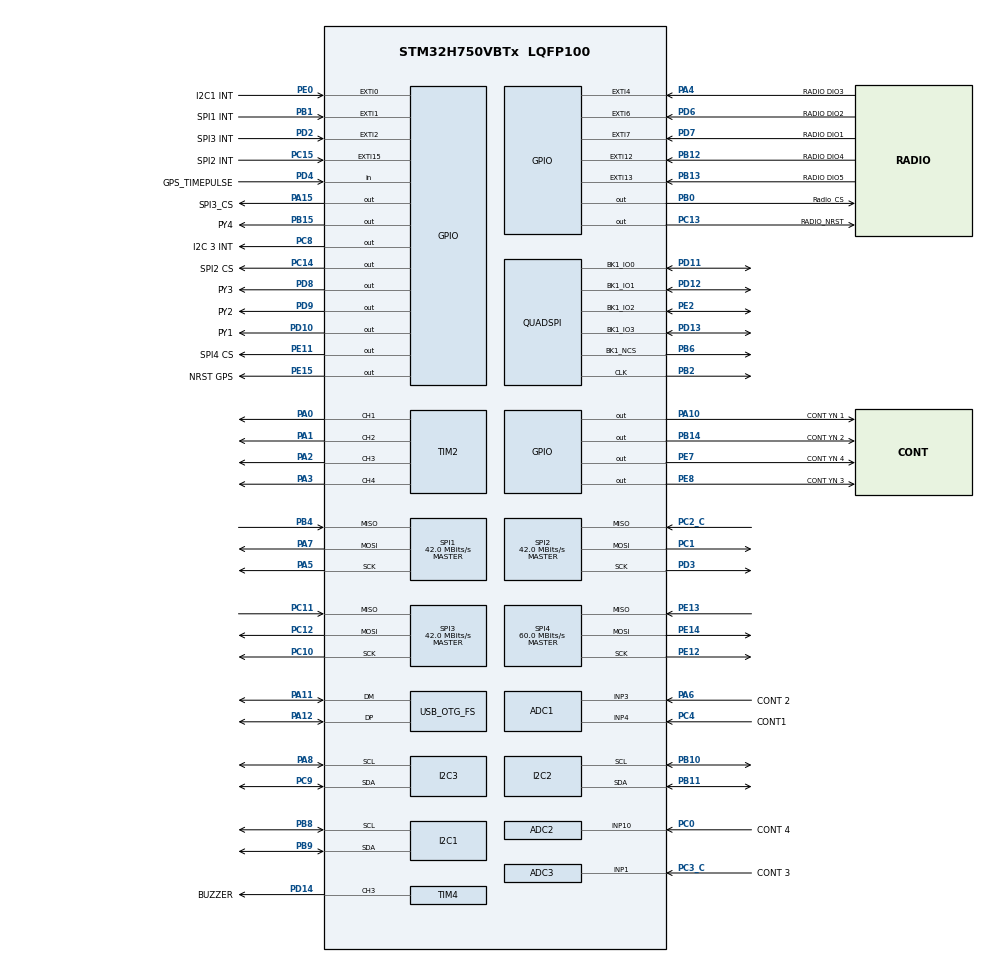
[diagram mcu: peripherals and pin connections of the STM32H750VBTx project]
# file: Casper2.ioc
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ADC1.Channel-2\#ChannelRegularConversion=ADC_CHANNEL_3
ADC1.ClockPrescaler=ADC_CLOCK_ASYNC_DIV2
ADC1.NbrOfConversionFlag=1
ADC1.OffsetNumber-2\#ChannelRegularConversion=ADC_OFFSET_NONE
ADC1.OffsetSignedSaturation-2\#ChannelRegularConversion=DISABLE
ADC1.Rank-2\#ChannelRegularConversion=1
ADC1.SamplingTime-2\#ChannelRegularConversion=ADC_SAMPLETIME_1CYCLE_5
ADC1.master=1
ADC2.Channel-1\#ChannelRegularConversion=ADC_CHANNEL_10
ADC2.ClockPrescaler=ADC_CLOCK_ASYNC_DIV2
ADC2.NbrOfConversionFlag=1
ADC2.OffsetNumber-1\#ChannelRegularConversion=ADC_OFFSET_NONE
ADC2.OffsetSignedSaturation-1\#ChannelRegularConversion=DISABLE
ADC2.Rank-1\#ChannelRegularConversion=1
ADC2.SamplingTime-1\#ChannelRegularConversion=ADC_SAMPLETIME_1CYCLE_5
ADC3.Channel-1\#ChannelRegularConversion=ADC_CHANNEL_1
ADC3.ClockPrescaler=ADC_CLOCK_ASYNC_DIV2
ADC3.NbrOfConversionFlag=1
ADC3.OffsetNumber-1\#ChannelRegularConversion=ADC_OFFSET_NONE
ADC3.OffsetSignedSaturation-1\#ChannelRegularConversion=DISABLE
ADC3.Rank-1\#ChannelRegularConversion=1
ADC3.SamplingTime-1\#ChannelRegularConversion=ADC_SAMPLETIME_1CYCLE_5
CORTEX_M7.default_mode_Activation=1
I2C1.Timing=0x10707DBC
I2C2.Timing=0x10707DBC
I2C3.Timing=0x10707DBC
Mcu.Family=STM32H7
Mcu.Name=STM32H750VBTx
Mcu.Package=LQFP100
NVIC.OTG_FS_EP1_IN_IRQn=true\:0\:0\:false\:false\:true\:true\:true\:true
NVIC.OTG_FS_EP1_OUT_IRQn=true\:0\:0\:false\:false\:true\:true\:true\:true
NVIC.OTG_FS_IRQn=true\:0\:0\:false\:false\:true\:true\:true\:true
NVIC.PriorityGroup=NVIC_PRIORITYGROUP_4
PA0.Signal=S_TIM2_CH1_ETR
PA1.Signal=S_TIM2_CH2
PA10.GPIO_Label=CONT YN 1
PA10.Signal=GPIO_Output
PA11.Mode=Device_Only
PA11.Signal=USB_OTG_FS_DM
PA12.Mode=Device_Only
PA12.Signal=USB_OTG_FS_DP
PA13\ (JTMS/SWDIO).Mode=Trace_Asynchronous_SW
PA13\ (JTMS/SWDIO).Signal=DEBUG_JTMS-SWDIO
PA14\ (JTCK/SWCLK).Mode=Trace_Asynchronous_SW
PA14\ (JTCK/SWCLK).Signal=DEBUG_JTCK-SWCLK
PA15\ (JTDI).GPIO_Label=SPI3_CS
PA15\ (JTDI).Signal=GPIO_Output
PA2.Signal=S_TIM2_CH3
PA3.Signal=S_TIM2_CH4
PA4.GPIO_Label=RADIO DIO3
PA4.Signal=GPXTI4
PA5.Mode=Full_Duplex_Master
PA5.Signal=SPI1_SCK
PA6.GPIO_Label=CONT 2
PA6.Signal=ADCx_INP3
PA7.Mode=Full_Duplex_Master
PA7.Signal=SPI1_MOSI
PA8.Mode=I2C
PA8.Signal=I2C3_SCL
PB0.GPIO_Label=Radio_CS
PB0.Signal=GPIO_Output
PB1.GPIO_Label=SPI1 INT
PB1.Signal=GPXTI1
PB10.Mode=I2C
PB10.Signal=I2C2_SCL
PB11.Mode=I2C
PB11.Signal=I2C2_SDA
PB12.GPIO_Label=RADIO DIO4
PB12.Signal=GPXTI12
PB13.GPIO_Label=RADIO DIO5
PB13.Signal=GPXTI13
PB14.GPIO_Label=CONT YN 2
PB14.Signal=GPIO_Output
PB15.GPIO_Label=PY4
PB15.Signal=GPIO_Output
PB2.Mode=Single Bank 1
PB2.Signal=QUADSPI_CLK
PB3\ (JTDO/TRACESWO).Mode=Trace_Asynchronous_SW
PB3\ (JTDO/TRACESWO).Signal=DEBUG_JTDO-SWO
PB4\ (NJTRST).Mode=Full_Duplex_Master
PB4\ (NJTRST).Signal=SPI1_MISO
PB6.Mode=Single Bank 1
PB6.Signal=QUADSPI_BK1_NCS
PB8.Mode=I2C
PB8.Signal=I2C1_SCL
PB9.Mode=I2C
PB9.Signal=I2C1_SDA
PC0.GPIO_Label=CONT 4
PC0.Signal=ADCx_INP10
PC1.Mode=Full_Duplex_Master
PC1.Signal=SPI2_MOSI
PC10.Mode=Full_Duplex_Master
PC10.Signal=SPI3_SCK
PC11.Mode=Full_Duplex_Master
PC11.Signal=SPI3_MISO
PC12.Mode=Full_Duplex_Master
PC12.Signal=SPI3_MOSI
PC13.GPIO_Label=RADIO_NRST
PC13.GPIO_PuPd=GPIO_PULLUP
PC13.Signal=GPIO_Output
PC14-OSC32_IN\ (OSC32_IN).GPIO_Label=SPI2 CS
PC14-OSC32_IN\ (OSC32_IN).Signal=GPIO_Output
PC15-OSC32_OUT\ (OSC32_OUT).GPIO_Label=SPI2 INT
PC15-OSC32_OUT\ (OSC32_OUT).Signal=GPXTI15
PC2_C.Mode=Full_Duplex_Master
PC2_C.Signal=SPI2_MISO
PC3_C.GPIO_Label=CONT 3
PC3_C.Mode=IN1-Single-Ended
PC3_C.Signal=ADC3_INP1
PC4.GPIO_Label=CONT1
PC4.Signal=ADCx_INP4
PC8.GPIO_Label=I2C 3 INT
PC8.Signal=GPIO_Output
PC9.Mode=I2C
PC9.Signal=I2C3_SDA
PD10.GPIO_Label=PY1
PD10.Signal=GPIO_Output
PD11.Mode=Single Bank 1
PD11.Signal=QUADSPI_BK1_IO0
PD12.Mode=Single Bank 1
PD12.Signal=QUADSPI_BK1_IO1
PD13.Mode=Single Bank 1
PD13.Signal=QUADSPI_BK1_IO3
PD14.GPIO_Label=BUZZER
PD14.Signal=S_TIM4_CH3
PD2.GPIO_Label=SPI3 INT
PD2.Signal=GPXTI2
PD3.Mode=Full_Duplex_Master
PD3.Signal=SPI2_SCK
PD4.GPIO_Label=GPS_TIMEPULSE
PD4.Signal=GPIO_Input
PD6.GPIO_Label=RADIO DIO2
PD6.Signal=GPXTI6
PD7.GPIO_Label=RADIO DIO1
PD7.Signal=GPXTI7
PD8.GPIO_Label=PY3
PD8.Signal=GPIO_Output
PD9.GPIO_Label=PY2
PD9.Signal=GPIO_Output
PE0.GPIO_Label=I2C1 INT
PE0.Signal=GPXTI0
PE11.GPIO_Label=SPI4 CS
PE11.Signal=GPIO_Output
PE12.Mode=Full_Duplex_Master
PE12.Signal=SPI4_SCK
PE13.Mode=Full_Duplex_Master
PE13.Signal=SPI4_MISO
PE14.Mode=Full_Duplex_Master
PE14.Signal=SPI4_MOSI
PE15.GPIO_Label=NRST GPS
PE15.GPIO_PuPd=GPIO_PULLUP
PE15.PinState=GPIO_PIN_SET
PE15.Signal=GPIO_Output
PE2.Mode=Single Bank 1
PE2.Signal=QUADSPI_BK1_IO2
PE7.GPIO_Label=CONT YN 4
PE7.Signal=GPIO_Output
PE8.GPIO_Label=CONT YN 3
PE8.Signal=GPIO_Output
PH0-OSC_IN\ (PH0).Mode=HSE-External-Oscillator
PH0-OSC_IN\ (PH0).Signal=RCC_OSC_IN
PH1-OSC_OUT\ (PH1).Mode=HSE-External-Oscillator
PH1-OSC_OUT\ (PH1).Signal=RCC_OSC_OUT
PWR.Mode=PWR_PVD_MODE_IT_RISING_FALLING
PWR.PVDLevel=PWR_PVDLEVEL_6
ProjectManager.HeapSize=0x200
ProjectManager.StackSize=0x400
ProjectManager.TargetToolchain=Makefile
RCC.ADCFreq_Value=84000000
RCC.APB1Freq_Value=120000000
RCC.APB2Freq_Value=120000000
RCC.APB3Freq_Value=120000000
RCC.APB4Freq_Value=120000000
RCC.CortexFreq_Value=480000000
RCC.D1PPRE=RCC_APB3_DIV2
RCC.D2PPRE1=RCC_APB1_DIV2
RCC.D2PPRE2=RCC_APB2_DIV2
RCC.D3PPRE=RCC_APB4_DIV2
RCC.DIVM1=6
RCC.DIVM2=2
RCC.DIVN1=240
RCC.DIVN2=14
RCC.DIVQ1=20
RCC.DIVR1=8
RCC.EnbaleCSS=true
RCC.HCLKFreq_Value=240000000
RCC.HPRE=RCC_HCLK_DIV2
RCC.HSE_VALUE=24000000
RCC.I2C123CLockSelection=RCC_I2C123CLKSOURCE_HSI
RCC.PLLSourceVirtual=RCC_PLLSOURCE_HSE
RCC.SDMMC1CLockSelection=RCC_SDMMCCLKSOURCE_PLL2
RCC.SPI123CLockSelection=RCC_SPI123CLKSOURCE_PLL2
RCC.SYSCLKFreq_VALUE=480000000
RCC.SYSCLKSource=RCC_SYSCLKSOURCE_PLLCLK
RCC.SupplySource=PWR_LDO_SUPPLY
RCC.USART234578CLockSelection=RCC_USART234578CLKSOURCE_PLL2
RCC.USBFreq_Value=48000000
SH.ADCx_INP10.0=ADC2_INP10,IN10-Single-Ended
SH.ADCx_INP3.0=ADC1_INP3,IN3-Single-Ended
SH.ADCx_INP4.0=ADC1_INP4,IN4-Single-Ended
SH.S_TIM2_CH1_ETR.0=TIM2_CH1,PWM Generation1 CH1
SH.S_TIM2_CH2.0=TIM2_CH2,PWM Generation2 CH2
SH.S_TIM2_CH3.0=TIM2_CH3,PWM Generation3 CH3
SH.S_TIM2_CH4.0=TIM2_CH4,PWM Generation4 CH4
SH.S_TIM4_CH3.0=TIM4_CH3,PWM Generation3 CH3
SPI1.BaudRatePrescaler=SPI_BAUDRATEPRESCALER_2
SPI1.CalculateBaudRate=42.0 MBits/s
SPI1.Direction=SPI_DIRECTION_2LINES
SPI1.Mode=SPI_MODE_MASTER
SPI1.VirtualType=VM_MASTER
SPI2.BaudRatePrescaler=SPI_BAUDRATEPRESCALER_2
SPI2.CLKPolarity=SPI_POLARITY_HIGH
SPI2.CalculateBaudRate=42.0 MBits/s
SPI2.DataSize=SPI_DATASIZE_8BIT
SPI2.Direction=SPI_DIRECTION_2LINES
SPI2.Mode=SPI_MODE_MASTER
SPI2.VirtualType=VM_MASTER
SPI3.BaudRatePrescaler=SPI_BAUDRATEPRESCALER_2
SPI3.CalculateBaudRate=42.0 MBits/s
SPI3.Direction=SPI_DIRECTION_2LINES
SPI3.Mode=SPI_MODE_MASTER
SPI3.VirtualType=VM_MASTER
SPI4.BaudRatePrescaler=SPI_BAUDRATEPRESCALER_2
SPI4.CalculateBaudRate=60.0 MBits/s
SPI4.Direction=SPI_DIRECTION_2LINES
SPI4.Mode=SPI_MODE_MASTER
SPI4.VirtualType=VM_MASTER
TIM2.Channel-PWM\ Generation1\ CH1=TIM_CHANNEL_1
TIM2.Channel-PWM\ Generation2\ CH2=TIM_CHANNEL_2
TIM2.Channel-PWM\ Generation3\ CH3=TIM_CHANNEL_3
TIM2.Channel-PWM\ Generation4\ CH4=TIM_CHANNEL_4
TIM4.Channel-PWM\ Generation3\ CH3=TIM_CHANNEL_3
USB_DEVICE.CLASS_NAME_FS=CDC
USB_DEVICE.VirtualMode-CDC_FS=Cdc
USB_DEVICE.VirtualModeFS=Cdc_FS
USB_OTG_FS.VirtualMode=Device_Only
VP_CRC_VS_CRC.Mode=CRC_Activate
VP_FATFS_VS_Generic.Mode=User_defined
VP_MEMORYMAP_VS_MEMORYMAP.Mode=CurAppReg
VP_PWR_V_PVD_IN.Mode=Mode_PVD_Int
VP_USB_DEVICE_VS_USB_DEVICE_CDC_FS.Mode=CDC_FS
board=custom

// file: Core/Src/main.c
/* USER CODE BEGIN Header */
/* ============================================================
 *  TIER:     CORE-FLIGHT
 *  MODULE:   Main / USB-mode dispatch
 *  SUMMARY:  Entry point; clock + peripheral init; USB_MODE branch select.
 * ============================================================ */
/**
  ******************************************************************************
  * @file           : main.c
  * @brief          : Main program body
  ******************************************************************************
  * @attention
  *
  * Copyright (c) 2026 STMicroelectronics.
  * All rights reserved.
  *
  * This software is licensed under terms that can be found in the LICENSE file
  * in the root directory of this software component.
  * If no LICENSE file comes with this software, it is provided AS-IS.
  *
  ******************************************************************************
  */
/* USER CODE END Header */
#include "main.h"
#include "fatfs.h"
#include "usb_device.h"

/* USER CODE BEGIN Includes */
#include <string.h>
#include <stdio.h>
#include <stdbool.h>
#if (USB_MODE != 2)
#include "usbd_cdc_if.h"
#endif
#include "ms5611.h"
#ifndef BUILD_TARGET_GROUND
#include "lsm6dso32.h"
#include "adxl372.h"
#include "w25q512jv.h"
#include "casper_ekf.h"
#include "casper_attitude.h"
#include "casper_quat.h"
#endif /* !BUILD_TARGET_GROUND */
#include "max_m10m.h"
#ifndef BUILD_TARGET_GROUND
#include "mmc5983ma.h"
#include "mag_cal.h"
#ifdef MAG_VAL
#include "mag_val.h"
#endif
#ifdef GYRO_TEMP_CAL
#include "temp_cal.h"
#endif
/* ── MC Testing / Telemetry modules ── */
#include "tlm_manager.h"
#include "cmd_router.h"
#include "cac_handler.h"
#include "cfg_manager.h"
#include "flight_fsm.h"
#include "pyro_manager.h"
#include "self_test.h"
#include "flight_loop.h"
#include "radio_manager.h"
#include "flight_logger.h"
#ifdef LOGGER_SANITY
#include "logger_sanity.h"
#include "cycle_probe.h"
#endif
#endif /* !BUILD_TARGET_GROUND */
#include "crc32_hw.h"
#include "radio_irq.h"
#include "buzzer.h"
#ifdef BUILD_TARGET_GROUND
#include "ground_main.h"
#endif
/* USER CODE END Includes */

/* USER CODE BEGIN PD */
#if defined(MAG_CAL) + defined(MAG_VAL) + defined(GYRO_TEMP_CAL) + defined(GPS_TEST) > 1
#error "Only one calibration/test mode may be defined at a time"
#endif

/* USER CODE END PD */

ADC_HandleTypeDef hadc1;
ADC_HandleTypeDef hadc2;
ADC_HandleTypeDef hadc3;

CRC_HandleTypeDef hcrc;

I2C_HandleTypeDef hi2c1;
I2C_HandleTypeDef hi2c2;
I2C_HandleTypeDef hi2c3;

QSPI_HandleTypeDef hqspi;

SPI_HandleTypeDef hspi1;
SPI_HandleTypeDef hspi2;
SPI_HandleTypeDef hspi3;
SPI_HandleTypeDef hspi4;

TIM_HandleTypeDef htim2;
TIM_HandleTypeDef htim4;

/* USER CODE BEGIN PV */
IWDG_HandleTypeDef hiwdg1;
ms5611_t baro;
#ifndef BUILD_TARGET_GROUND
lsm6dso32_t imu;
adxl372_t high_g;
w25q512jv_t flash;
casper_ekf_t ekf;
casper_attitude_t att;
#endif
max_m10m_t gps;
#ifndef BUILD_TARGET_GROUND
mmc5983ma_t mag;
flight_logger_t logger;
#endif
/* USER CODE END PV */

void SystemClock_Config(void);
void PeriphCommonClock_Config(void);
static void MPU_Config(void);
static void MX_GPIO_Init(void);
static void MX_ADC1_Init(void);
static void MX_ADC2_Init(void);
static void MX_ADC3_Init(void);
static void MX_I2C1_Init(void);
static void MX_I2C2_Init(void);
static void MX_QUADSPI_Init(void);
static void MX_SPI1_Init(void);
static void MX_SPI2_Init(void);
static void MX_SPI4_Init(void);
static void MX_TIM2_Init(void);
static void MX_CRC_Init(void);
static void MX_TIM4_Init(void);
static void MX_I2C3_Init(void);
static void MX_SPI3_Init(void);
/* USER CODE BEGIN PFP */
static void MX_IWDG1_Init(void);
/* USER CODE END PFP */

/* USER CODE BEGIN 0 */
static void MX_IWDG1_Init(void)
{
    /* LSI ~32 kHz, /4 -> 8 kHz, reload 3999 -> 500ms timeout */
    hiwdg1.Instance  = IWDG1;
    hiwdg1.Prescaler = 0;     /* PR=0 -> /4 */
    hiwdg1.Reload    = 3999;
    HAL_IWDG_Init(&hiwdg1);
}
/* USER CODE END 0 */

int main(void)
{

  /* MPU Configuration--------------------------------------------------------*/
  MPU_Config();

  /* MCU Configuration--------------------------------------------------------*/

  /* Reset of all peripherals, Initializes the Flash interface and the Systick. */
  HAL_Init();

  /* USER CODE BEGIN Init */
  // Enable GPIO clocks for all 4 LEDs
  RCC->AHB4ENR |= RCC_AHB4ENR_GPIOAEN | RCC_AHB4ENR_GPIOBEN | RCC_AHB4ENR_GPIOEEN;
  (void)RCC->AHB4ENR;

  // Configure all 4 LED pins as GP output (MODER = 01)
  GPIOA->MODER = (GPIOA->MODER & ~(3UL << (10*2))) | (1UL << (10*2)); // PA10
  GPIOB->MODER = (GPIOB->MODER & ~(3UL << (14*2))) | (1UL << (14*2)); // PB14
  GPIOE->MODER = (GPIOE->MODER & ~(3UL << (8*2)))  | (1UL << (8*2));  // PE8
  GPIOE->MODER = (GPIOE->MODER & ~(3UL << (7*2)))  | (1UL << (7*2));  // PE7

  // Milestone 1: HAL_Init passed
  GPIOA->BSRR = (1UL << 10);  // LED1 ON
  HAL_Delay(500);
  /* USER CODE END Init */

  /* Configure the system clock */
  SystemClock_Config();

  /* Configure the peripherals common clocks */
  PeriphCommonClock_Config();

  /* USER CODE BEGIN SysInit */
  /* Enable the Cortex-M7 DWT free-running cycle counter (DWT->CYCCNT).
   * Used by:
   *   - flight_loop.c adaptive-dt: actual elapsed time per IMU sample,
   *     fed to attitude estimator and EKF predict instead of a fixed
   *     EKF_DT constant. Critical for estimator correctness.
   *   - LOGGER_SANITY cycle probes (when enabled) — performance
   *     measurement of the hot paths.
   * Cost: zero — DWT runs from SYSCLK with no software intervention. */
  CoreDebug->DEMCR |= CoreDebug_DEMCR_TRCENA_Msk;
  DWT->LAR    = 0xC5ACCE55u;            /* H7 lock register magic */
  DWT->CYCCNT = 0;
  DWT->CTRL  |= DWT_CTRL_CYCCNTENA_Msk;
  /* USER CODE END SysInit */

  /* Initialize all configured peripherals */
  MX_GPIO_Init();
  MX_ADC1_Init();
  MX_ADC2_Init();
  MX_ADC3_Init();
  MX_I2C1_Init();
#ifndef BUILD_TARGET_GROUND
  MX_I2C2_Init();
  MX_QUADSPI_Init();
#endif
  MX_SPI1_Init();
#ifndef BUILD_TARGET_GROUND
  MX_SPI2_Init();
#endif
  MX_SPI4_Init();
  MX_TIM2_Init();
  MX_CRC_Init();
  MX_TIM4_Init();
#ifndef BUILD_TARGET_GROUND
  MX_I2C3_Init();
  MX_SPI3_Init();

  // Init flash BEFORE USB so MSC storage callbacks can respond during enumeration
  w25q512jv_init(&flash, &hqspi);
#endif

  MX_USB_DEVICE_Init();
#ifndef BUILD_TARGET_GROUND
  MX_FATFS_Init();
#endif
  /* USER CODE BEGIN 2 */

  /* ── 5-second USB enumeration window ──
   * Wait here so the user can open a serial terminal before any
   * sensor init runs.  All CDC debug prints after this point will
   * be visible. */
  HAL_Delay(5000);

#ifdef BUILD_TARGET_GROUND
  /* ── Ground station init ──────────────────────────────────────── */
  {
    char _dbg[80]; int _len;
    #define DBG_PRINT(msg) do { \
      _len = snprintf(_dbg, sizeof(_dbg), msg); \
      CDC_Transmit_FS((uint8_t *)_dbg, (uint16_t)_len); \
      HAL_Delay(20); \
    } while(0)

    DBG_PRINT("[INIT] Ground station mode\r\n");
    DBG_PRINT("[INIT] MS5611...\r\n");
    if (!ms5611_init(&baro, &hspi4, SPI4_CS_GPIO_Port, SPI4_CS_Pin)) {
      for (int i = 0; i < 6; i++) {
        HAL_GPIO_TogglePin(CONT_YN_3_GPIO_Port, CONT_YN_3_Pin);
        HAL_GPIO_TogglePin(CONT_YN_4_GPIO_Port, CONT_YN_4_Pin);
        HAL_Delay(200);
      }
    }
    ms5611_set_oversampling(&baro, MS5611_OSR_2048);

    DBG_PRINT("[INIT] GPS...\r\n");
    if (!max_m10m_init(&gps, &hi2c1, NRST_GPS_GPIO_Port, NRST_GPS_Pin)) {
      for (int i = 0; i < 6; i++) {
        HAL_GPIO_TogglePin(CONT_YN_3_GPIO_Port, CONT_YN_3_Pin);
        HAL_GPIO_TogglePin(CONT_YN_4_GPIO_Port, CONT_YN_4_Pin);
        HAL_Delay(200);
      }
    }

    DBG_PRINT("[INIT] CRC + radio...\r\n");
    crc32_hw_init();
    buzzer_init(&htim4);

    DBG_PRINT("[INIT] ground_main_init...\r\n");
    ground_main_init(&hspi1, &baro, &gps);

    DBG_PRINT("[INIT] Ground station init complete\r\n");
  }

  /* Enable EXTI1 for SX1276 DIO0 (PB1) */
  __HAL_GPIO_EXTI_CLEAR_IT(SPI1_INT_Pin);
  HAL_NVIC_SetPriority(EXTI1_IRQn, 5, 0);
  HAL_NVIC_EnableIRQ(EXTI1_IRQn);

  /* Enable EXTI9_5 for DIO1 (PD7) */
  __HAL_GPIO_EXTI_CLEAR_IT(RADIO_DIO1_Pin);
  HAL_NVIC_SetPriority(EXTI9_5_IRQn, 5, 1);
  HAL_NVIC_EnableIRQ(EXTI9_5_IRQn);

  /* Reset pyro pins to input mode (safety — GS has no pyros) */
  {
    GPIO_InitTypeDef pyro_safe = {0};
    pyro_safe.Pin = PY1_Pin | PY2_Pin | PY3_Pin;
    pyro_safe.Mode = GPIO_MODE_INPUT;
    pyro_safe.Pull = GPIO_PULLDOWN;
    HAL_GPIO_Init(GPIOD, &pyro_safe);

    pyro_safe.Pin = PY4_Pin;
    HAL_GPIO_Init(GPIOB, &pyro_safe);
  }

#else /* FLIGHT build — existing code unchanged */

  {
    char _dbg[80]; int _len;
#if (USB_MODE == 2)
    #define DBG_PRINT(msg) do { (void)_dbg; (void)_len; } while(0)
#else
    #define DBG_PRINT(msg) do { \
      _len = snprintf(_dbg, sizeof(_dbg), msg); \
      CDC_Transmit_FS((uint8_t *)_dbg, (uint16_t)_len); \
      HAL_Delay(20); \
    } while(0)
#endif

    DBG_PRINT("[INIT] USB up, starting sensor init\r\n");

    // M1: MS5611
    DBG_PRINT("[INIT] MS5611...\r\n");

  // Init MS5611 barometer on SPI4
  if (!ms5611_init(&baro, &hspi4, SPI4_CS_GPIO_Port, SPI4_CS_Pin)) {
    // PROM read failed — blink LED3+LED4 as warning but continue
    for (int i = 0; i < 6; i++) {
      HAL_GPIO_TogglePin(CONT_YN_3_GPIO_Port, CONT_YN_3_Pin);
      HAL_GPIO_TogglePin(CONT_YN_4_GPIO_Port, CONT_YN_4_Pin);
      HAL_Delay(200);
    }
  }
#ifdef GYRO_TEMP_CAL
  ms5611_set_oversampling(&baro, MS5611_OSR_4096);
#else
  ms5611_set_oversampling(&baro, MS5611_OSR_2048);
#endif

    DBG_PRINT("[INIT] MS5611 done\r\n");

  // Explicitly close PC2 analog switch for SPI2 MISO (PC2_C)
  HAL_SYSCFG_AnalogSwitchConfig(SYSCFG_SWITCH_PC2, SYSCFG_SWITCH_PC2_CLOSE);

  // Fix PC2 MODER: something during init sets PC2 to analog mode instead of AF.
  {
    GPIO_InitTypeDef gpio_fix = {0};
    gpio_fix.Pin = GPIO_PIN_2;
    gpio_fix.Mode = GPIO_MODE_AF_PP;
    gpio_fix.Pull = GPIO_NOPULL;
    gpio_fix.Speed = GPIO_SPEED_FREQ_LOW;
    gpio_fix.Alternate = GPIO_AF5_SPI2;
    HAL_GPIO_Init(GPIOC, &gpio_fix);
  }

    DBG_PRINT("[INIT] LSM6DSO32...\r\n");

  // Init LSM6DSO32 IMU on SPI2
  lsm6dso32_init(&imu, &hspi2, SPI2_CS_GPIO_Port, SPI2_CS_Pin);
  if (imu.device_id != LSM6DSO32_WHO_AM_I_VAL) {
    // WHO_AM_I mismatch — blink LED3+LED4 as warning but continue
    for (int i = 0; i < 6; i++) {
      HAL_GPIO_TogglePin(CONT_YN_3_GPIO_Port, CONT_YN_3_Pin);
      HAL_GPIO_TogglePin(CONT_YN_4_GPIO_Port, CONT_YN_4_Pin);
      HAL_Delay(200);
    }
  }

    DBG_PRINT("[INIT] LSM6DSO32 done\r\n");

  // NOTE: EXTI15 for LSM6DSO32 INT2 deferred to after all init completes
  // (enabling it here caused immediate ISR hang — INT2 already asserted)

    DBG_PRINT("[INIT] EKF+attitude...\r\n");
  {
    casper_att_config_t att_cfg = {
      .Kp_grav           = 10.0f,
      .Kp_mag_pad        = 0.0f,
      .Kp_mag_flight     = 0.0f,
      .Ki                = 0.0f,   /* integral disabled — bias handled by EMA estimator; avoids windup-driven heading drift */
      .gyro_lpf_cutoff_hz = 50.0f,
      .mag_update_hz     = 10.0f,
      .launch_accel_g    = 3.0f,
    };
    casper_att_init(&att, &att_cfg);
    casper_ekf_init(&ekf);
  }

    DBG_PRINT("[INIT] ADXL372...\r\n");
  adxl372_init(&high_g, &hspi3, SPI3_CS_GPIO_Port, SPI3_CS_Pin);
  if (high_g.device_id != ADXL372_DEVID_VAL) {
    for (int i = 0; i < 6; i++) {
      HAL_GPIO_TogglePin(CONT_YN_3_GPIO_Port, CONT_YN_3_Pin);
      HAL_GPIO_TogglePin(CONT_YN_4_GPIO_Port, CONT_YN_4_Pin);
      HAL_Delay(200);
    }
  }
  if (high_g.device_id == ADXL372_DEVID_VAL) {
    adxl372_wakeup_init(&high_g, ADXL_LAUNCH_G, 6);
  }

    DBG_PRINT("[INIT] GPS...\r\n");
#ifndef GYRO_TEMP_CAL
#ifdef GPS_TEST
  /* Minimal init — no UBX config, just reset + I2C check.
   * Module outputs default NMEA which we passthrough to CDC. */
  if (!max_m10m_init_minimal(&gps, &hi2c1, NRST_GPS_GPIO_Port, NRST_GPS_Pin)) {
    for (int i = 0; i < 6; i++) {
      HAL_GPIO_TogglePin(CONT_YN_3_GPIO_Port, CONT_YN_3_Pin);
      HAL_GPIO_TogglePin(CONT_YN_4_GPIO_Port, CONT_YN_4_Pin);
      HAL_Delay(200);
    }
  }
  if (gps.alive) {
    bool cfg_ok = max_m10m_configure_gps_test(&gps);
    bool rf_ok  = max_m10m_poll_mon_rf(&gps);
    {
      char _msg[160]; int _ml;
      static const char *ant_str[] = {"INIT","DONTKNOW","OK","SHORT","OPEN"};
      static const char *pwr_str[] = {"OFF","ON","DONTKNOW"};
      if (rf_ok) {
        _ml = snprintf(_msg, sizeof(_msg),
          "[INIT] GPS cfg=%s ant=%s pwr=%s noise=%u agc=%u jam=%u\r\n",
          cfg_ok ? "OK" : "FAIL",
          gps.ant_status <= 4 ? ant_str[gps.ant_status] : "?",
          gps.ant_power <= 2 ? pwr_str[gps.ant_power] : "?",
          gps.rf_noise_per_ms, gps.rf_agc_cnt, gps.rf_jam_ind);
      } else {
        _ml = snprintf(_msg, sizeof(_msg),
          "[INIT] GPS cfg=%s (MON-RF timeout)\r\n",
          cfg_ok ? "OK" : "FAIL");
      }
      CDC_Transmit_FS((uint8_t *)_msg, (uint16_t)_ml);
      HAL_Delay(20);
    }
  }
#else
  if (!max_m10m_init(&gps, &hi2c1, NRST_GPS_GPIO_Port, NRST_GPS_Pin)) {
    for (int i = 0; i < 6; i++) {
      HAL_GPIO_TogglePin(CONT_YN_3_GPIO_Port, CONT_YN_3_Pin);
      HAL_GPIO_TogglePin(CONT_YN_4_GPIO_Port, CONT_YN_4_Pin);
      HAL_Delay(200);
    }
  }
#endif
#endif

  // Reconfigure I2C_3_INT (PC8) from output to EXTI rising edge
  {
    GPIO_InitTypeDef gpio_fix = {0};
    gpio_fix.Pin = I2C_3_INT_Pin;
    gpio_fix.Mode = GPIO_MODE_IT_RISING;
    gpio_fix.Pull = GPIO_NOPULL;
    HAL_GPIO_Init(I2C_3_INT_GPIO_Port, &gpio_fix);
  }

    DBG_PRINT("[INIT] MMC5983MA...\r\n");
#ifdef GYRO_TEMP_CAL
  mmc5983ma_init_oneshot(&mag, &hi2c3);
#else
  mmc5983ma_init(&mag, &hi2c3);
#endif
  if (mag.product_id != MMC5983MA_PROD_ID_VAL) {
    for (int i = 0; i < 6; i++) {
      HAL_GPIO_TogglePin(CONT_YN_3_GPIO_Port, CONT_YN_3_Pin);
      HAL_GPIO_TogglePin(CONT_YN_4_GPIO_Port, CONT_YN_4_Pin);
      HAL_Delay(200);
    }
  }

    DBG_PRINT("[INIT] telemetry+FSM+pyro+buzzer...\r\n");
  crc32_hw_init();
  tlm_init();
  cmd_router_init();
  cac_init();
  cfg_manager_init();
  flight_fsm_init();
  pyro_mgr_init(&hadc1, &hadc2, &hadc3);
#ifndef GPS_TEST
  buzzer_init(&htim4);
#endif

    DBG_PRINT("[INIT] radio...\r\n");
  int radio_init_ok = 0;
  {
    int rc = radio_manager_init(&hspi1);
    radio_init_ok = (rc == 0);
#if (USB_MODE != 2)
    _len = snprintf(_dbg, sizeof(_dbg), "[INIT] radio returned %d\r\n", rc);
    CDC_Transmit_FS((uint8_t *)_dbg, (uint16_t)_len);
    HAL_Delay(20);
#endif

    if (rc != 0) {
      for (int i = 0; i < 10; i++) {
        HAL_GPIO_TogglePin(CONT_YN_3_GPIO_Port, CONT_YN_3_Pin);
        HAL_GPIO_TogglePin(CONT_YN_4_GPIO_Port, CONT_YN_4_Pin);
        HAL_Delay(100);
      }
      HAL_GPIO_WritePin(CONT_YN_3_GPIO_Port, CONT_YN_3_Pin, GPIO_PIN_RESET);
      HAL_GPIO_WritePin(CONT_YN_4_GPIO_Port, CONT_YN_4_Pin, GPIO_PIN_RESET);
    }
  }

  /* Flight data logger init (reads flight index, sets up ring buffers) */
  flight_logger_init(&logger, &flash);

    DBG_PRINT("[INIT] all init complete\r\n");

#ifndef GPS_TEST
  /* Startup beep: 3 short = radio OK, 5 long = radio FAIL */
  if (radio_init_ok) {
    buzzer_beep_n(50, 3, 100, 150);
  } else {
    buzzer_beep_n(50, 5, 300, 100);
  }
#endif

  } /* end DBG_PRINT scope */

  /* EXTI15_10 (PC15 = LSM6DSO32 INT2):
   *   Originally disabled because SX1276 DIO4 (PB12) / DIO5 (PB13) were
   *   configured as IT_RISING by CubeMX and toggled constantly,
   *   producing stale-pending interrupts that flooded EXTI15_10.
   *   Fix applied in MX_GPIO_Init_2 USER block: PB12/PB13 are now plain
   *   inputs, so EXTI15_10 only ever fires for PC15.  Enable the NVIC
   *   line and clear any pending bit before enabling. */
  __HAL_GPIO_EXTI_CLEAR_IT(SPI2_INT_Pin);
  HAL_NVIC_SetPriority(EXTI15_10_IRQn, 5, 2);
  HAL_NVIC_EnableIRQ(EXTI15_10_IRQn);

  // Check flash init result (already initialized before USB)
  bool flash_ok = false;
  if (flash.jedec_id[0] != W25Q512JV_MANUFACTURER_ID) {
    for (int i = 0; i < 6; i++) {
      HAL_GPIO_TogglePin(CONT_YN_3_GPIO_Port, CONT_YN_3_Pin);
      HAL_GPIO_TogglePin(CONT_YN_4_GPIO_Port, CONT_YN_4_Pin);
      HAL_Delay(200);
    }
  } else {
    flash_ok = true;
  }
  (void)flash_ok;  // suppress warning when FATFS block is compiled out

#if (USB_MODE != 2)
  bool fatfs_ok = false;
  bool file_test_ok = false;
  /* FATFS now lives in a 4 MB partition at the top of flash
   * (FATFS_FLASH_BASE = 0x03C00000), separate from the flight log region.
   * f_mkfs and FATFS writes only ever touch that partition, so this init
   * is safe in every build. */
#if (TEST_MODE != 1)
  if (flash_ok) {
    FRESULT fres = f_mount(&USERFatFS, USERPath, 1);
    if (fres == FR_NO_FILESYSTEM) {
      // First boot — format the flash with FAT
      BYTE work[4096];
      fres = f_mkfs(USERPath, FM_FAT, 0, work, sizeof(work));
      if (fres == FR_OK)
        fres = f_mount(&USERFatFS, USERPath, 1);
    }
    fatfs_ok = (fres == FR_OK);
  }

  // File I/O test: write a string, read it back, compare
  if (fatfs_ok) {
    const char test_str[] = "CASPER-2 FATFS OK";
    char read_buf[32] = {0};
    UINT bw = 0, br = 0;
    FRESULT fr;

    // Write test file
    fr = f_open(&USERFile, "TEST.TXT", FA_CREATE_ALWAYS | FA_WRITE);
    if (fr == FR_OK) {
      fr = f_write(&USERFile, test_str, sizeof(test_str) - 1, &bw);
      f_close(&USERFile);
    }

    // Read it back
    if (fr == FR_OK && bw == sizeof(test_str) - 1) {
      fr = f_open(&USERFile, "TEST.TXT", FA_READ);
      if (fr == FR_OK) {
        fr = f_read(&USERFile, read_buf, sizeof(test_str) - 1, &br);
        f_close(&USERFile);
      }
    }

    // Verify
    if (fr == FR_OK && br == sizeof(test_str) - 1 &&
        memcmp(test_str, read_buf, br) == 0) {
      file_test_ok = true;
    }
  }
#endif /* TEST_MODE != 1 */
#endif /* USB_MODE != 2 */

  /* DEBUG: LED4 ON = FATFS done */
  HAL_GPIO_WritePin(CONT_YN_4_GPIO_Port, CONT_YN_4_Pin, GPIO_PIN_SET);

  // M5: init complete — all LEDs off, then blink all 3 times
  HAL_GPIO_WritePin(CONT_YN_1_GPIO_Port, CONT_YN_1_Pin, GPIO_PIN_RESET);
  HAL_GPIO_WritePin(CONT_YN_2_GPIO_Port, CONT_YN_2_Pin, GPIO_PIN_RESET);
  HAL_GPIO_WritePin(CONT_YN_3_GPIO_Port, CONT_YN_3_Pin, GPIO_PIN_RESET);
  HAL_GPIO_WritePin(CONT_YN_4_GPIO_Port, CONT_YN_4_Pin, GPIO_PIN_RESET);
  for (int i = 0; i < 3; i++) {
    HAL_GPIO_WritePin(CONT_YN_1_GPIO_Port, CONT_YN_1_Pin, GPIO_PIN_SET);
    HAL_GPIO_WritePin(CONT_YN_2_GPIO_Port, CONT_YN_2_Pin, GPIO_PIN_SET);
    HAL_GPIO_WritePin(CONT_YN_3_GPIO_Port, CONT_YN_3_Pin, GPIO_PIN_SET);
    HAL_GPIO_WritePin(CONT_YN_4_GPIO_Port, CONT_YN_4_Pin, GPIO_PIN_SET);
    HAL_Delay(150);
    HAL_GPIO_WritePin(CONT_YN_1_GPIO_Port, CONT_YN_1_Pin, GPIO_PIN_RESET);
    HAL_GPIO_WritePin(CONT_YN_2_GPIO_Port, CONT_YN_2_Pin, GPIO_PIN_RESET);
    HAL_GPIO_WritePin(CONT_YN_3_GPIO_Port, CONT_YN_3_Pin, GPIO_PIN_RESET);
    HAL_GPIO_WritePin(CONT_YN_4_GPIO_Port, CONT_YN_4_Pin, GPIO_PIN_RESET);
    HAL_Delay(150);
  }
  HAL_Delay(500);  // USB enumeration time

#if (USB_MODE != 2)
  // Print status on first few lines so terminal can capture it
  {
    char info_buf[160];
    int info_len = snprintf(info_buf, sizeof(info_buf),
        ">who:0x%02X,adxl:0x%02X,mag:0x%02X,flash_id:0x%02X%02X%02X,fatfs:%s,file_test:%s,gps:%s\r\n",
        imu.device_id, high_g.device_id, mag.product_id,
        flash.jedec_id[0], flash.jedec_id[1], flash.jedec_id[2],
        fatfs_ok ? "OK" : "ERR",
        file_test_ok ? "PASS" : "FAIL",
        gps.alive ? "OK" : "NO_ACK");
    for (int i = 0; i < 5; i++) {
      CDC_Transmit_FS((uint8_t *)info_buf, info_len);
      HAL_Delay(200);
    }
  }
  // Print MS5611 raw PROM calibration coefficients
  {
    char prom_buf[100];
    int prom_len = snprintf(prom_buf, sizeof(prom_buf),
        ">PROM:C0=%u,C1=%u,C2=%u,C3=%u,C4=%u,C5=%u,C6=%u\r\n",
        baro.prom[0], baro.prom[1], baro.prom[2],
        baro.prom[3], baro.prom[4], baro.prom[5], baro.prom[6]);
    for (int i = 0; i < 3; i++) {
      CDC_Transmit_FS((uint8_t *)prom_buf, prom_len);
      HAL_Delay(200);
    }
  }
#endif /* USB_MODE != 2 */

#if (USB_MODE == 2)
  /* MSC mode: LEDs now driven by pyro_tick for continuity — all off initially */
  HAL_GPIO_WritePin(CONT_YN_1_GPIO_Port, CONT_YN_1_Pin, GPIO_PIN_RESET);
  HAL_GPIO_WritePin(CONT_YN_2_GPIO_Port, CONT_YN_2_Pin, GPIO_PIN_RESET);
  HAL_GPIO_WritePin(CONT_YN_3_GPIO_Port, CONT_YN_3_Pin, GPIO_PIN_RESET);
  HAL_GPIO_WritePin(CONT_YN_4_GPIO_Port, CONT_YN_4_Pin, GPIO_PIN_RESET);
#else
  /* Clear all LEDs before calibration sequence */
  HAL_GPIO_WritePin(CONT_YN_1_GPIO_Port, CONT_YN_1_Pin, GPIO_PIN_RESET);
  HAL_GPIO_WritePin(CONT_YN_2_GPIO_Port, CONT_YN_2_Pin, GPIO_PIN_RESET);
  HAL_GPIO_WritePin(CONT_YN_3_GPIO_Port, CONT_YN_3_Pin, GPIO_PIN_RESET);
  HAL_GPIO_WritePin(CONT_YN_4_GPIO_Port, CONT_YN_4_Pin, GPIO_PIN_RESET);
#endif

#ifdef MAG_CAL
  mag_cal_t mcal;
  if (!mag_cal_init(&mcal)) {
    /* File open failed — rapid blink all LEDs */
    while (1) {
      HAL_GPIO_TogglePin(CONT_YN_1_GPIO_Port, CONT_YN_1_Pin);
      HAL_GPIO_TogglePin(CONT_YN_2_GPIO_Port, CONT_YN_2_Pin);
      HAL_GPIO_TogglePin(CONT_YN_3_GPIO_Port, CONT_YN_3_Pin);
      HAL_GPIO_TogglePin(CONT_YN_4_GPIO_Port, CONT_YN_4_Pin);
      HAL_Delay(100);
    }
  }
#endif
#ifdef MAG_VAL
  mag_val_t mval;
  if (!mag_val_init(&mval)) {
    while (1) {
      HAL_GPIO_TogglePin(CONT_YN_1_GPIO_Port, CONT_YN_1_Pin);
      HAL_GPIO_TogglePin(CONT_YN_2_GPIO_Port, CONT_YN_2_Pin);
      HAL_GPIO_TogglePin(CONT_YN_3_GPIO_Port, CONT_YN_3_Pin);
      HAL_GPIO_TogglePin(CONT_YN_4_GPIO_Port, CONT_YN_4_Pin);
      HAL_Delay(100);
    }
  }
#elif defined(GYRO_TEMP_CAL)
  temp_cal_t tcal;
  if (!temp_cal_init(&tcal)) {
    /* File open failed — rapid blink all LEDs */
    while (1) {
      HAL_GPIO_TogglePin(CONT_YN_1_GPIO_Port, CONT_YN_1_Pin);
      HAL_GPIO_TogglePin(CONT_YN_2_GPIO_Port, CONT_YN_2_Pin);
      HAL_GPIO_TogglePin(CONT_YN_3_GPIO_Port, CONT_YN_3_Pin);
      HAL_GPIO_TogglePin(CONT_YN_4_GPIO_Port, CONT_YN_4_Pin);
      HAL_Delay(100);
    }
  }
#else
  /* IWDG: 500ms timeout (LSI ~32kHz, /4 -> 8kHz, reload 3999 -> 500ms).
   * Started here — after all blocking init — so USB enumeration + sensor
   * init cannot trip it.  flight_loop_tick() kicks it every iteration. */
  MX_IWDG1_Init();
  flight_loop_init();
  flight_logger_start(&logger);  /* Begin PAD-state ring filling + erase-ahead */
#ifdef LOGGER_SANITY
  logger_sanity_init(&logger);
#endif
#endif

#endif /* BUILD_TARGET_GROUND */
  /* USER CODE END 2 */

  /* Infinite loop */
  while (1)
  {

    /* USER CODE BEGIN 3 */
#if defined(BUILD_TARGET_GROUND)
    ground_main_tick();
#elif (USB_MODE == 2)
    buzzer_tick();
    // MSC mode: pyro continuity LEDs at 10 Hz (replaces old ping-pong)
    {
      static uint32_t last_pyro_tick = 0;
      if (HAL_GetTick() - last_pyro_tick >= 100) {
        pyro_mgr_tick();
        last_pyro_tick = HAL_GetTick();
      }
    }
#elif defined(MAG_CAL)
    {
      static uint32_t last_mag_tick = 0;
      uint32_t now = HAL_GetTick();

      /* 100 Hz mag read + calibration tick */
      if (now - last_mag_tick >= 10) {
        mmc5983ma_read(&mag);
        mag_cal_tick(&mcal, &mag, now);
        last_mag_tick = now;
      }

      /* Done: all LEDs solid, print final message, idle forever */
      if (mag_cal_is_done(&mcal)) {
        HAL_GPIO_WritePin(CONT_YN_1_GPIO_Port, CONT_YN_1_Pin, GPIO_PIN_SET);
        HAL_GPIO_WritePin(CONT_YN_2_GPIO_Port, CONT_YN_2_Pin, GPIO_PIN_SET);
        HAL_GPIO_WritePin(CONT_YN_3_GPIO_Port, CONT_YN_3_Pin, GPIO_PIN_SET);
        HAL_GPIO_WritePin(CONT_YN_4_GPIO_Port, CONT_YN_4_Pin, GPIO_PIN_SET);
        char done_buf[64];
        int done_len = snprintf(done_buf, sizeof(done_buf),
            ">mag_cal: DONE (%lu samples)\r\n", mcal.sample_count);
        for (int i = 0; i < 5; i++) {
          CDC_Transmit_FS((uint8_t *)done_buf, done_len);
          HAL_Delay(200);
        }
        while (1) { HAL_Delay(1000); }
      }
    }
#elif defined(MAG_VAL)
    {
      static uint32_t last_mag_tick = 0;
      uint32_t now = HAL_GetTick();

      /* 100 Hz mag read + validation tick */
      if (now - last_mag_tick >= 10) {
        mmc5983ma_read(&mag);
        mag_val_tick(&mval, &mag, now);
        last_mag_tick = now;
      }

      /* Done: all LEDs solid, print final message, idle forever */
      if (mag_val_is_done(&mval)) {
        HAL_GPIO_WritePin(CONT_YN_1_GPIO_Port, CONT_YN_1_Pin, GPIO_PIN_SET);
        HAL_GPIO_WritePin(CONT_YN_2_GPIO_Port, CONT_YN_2_Pin, GPIO_PIN_SET);
        HAL_GPIO_WritePin(CONT_YN_3_GPIO_Port, CONT_YN_3_Pin, GPIO_PIN_SET);
        HAL_GPIO_WritePin(CONT_YN_4_GPIO_Port, CONT_YN_4_Pin, GPIO_PIN_SET);
        char done_buf[64];
        int done_len = snprintf(done_buf, sizeof(done_buf),
            ">mag_val: DONE (%lu samples)\r\n", mval.sample_count);
        for (int i = 0; i < 5; i++) {
          CDC_Transmit_FS((uint8_t *)done_buf, done_len);
          HAL_Delay(200);
        }
        while (1) { HAL_Delay(1000); }
      }
    }
#elif defined(GYRO_TEMP_CAL)
    {
      static uint32_t last_tcal_tick = 0;
      uint32_t now = HAL_GetTick();

      /* 10 Hz: sample all sensors + log to CSV */
      if (now - last_tcal_tick >= 100) {
        temp_cal_tick(&tcal, &imu, &baro, &mag, now);
        last_tcal_tick = now;
      }

      /* Stopped: all LEDs solid, idle forever */
      if (temp_cal_is_stopped(&tcal)) {
        HAL_GPIO_WritePin(CONT_YN_1_GPIO_Port, CONT_YN_1_Pin, GPIO_PIN_SET);
        HAL_GPIO_WritePin(CONT_YN_2_GPIO_Port, CONT_YN_2_Pin, GPIO_PIN_SET);
        HAL_GPIO_WritePin(CONT_YN_3_GPIO_Port, CONT_YN_3_Pin, GPIO_PIN_SET);
        HAL_GPIO_WritePin(CONT_YN_4_GPIO_Port, CONT_YN_4_Pin, GPIO_PIN_SET);
        while (1) { HAL_Delay(1000); }
      }
    }
#elif defined(GPS_TEST)
    {
      static uint32_t last_status = 0;
      uint32_t now = HAL_GetTick();

      /* NMEA passthrough: read I2C, forward complete lines to CDC */
      max_m10m_tick_nmea(&gps);

      if (gps.nmea_line_ready) {
        gps.nmea_line_ready = false;
        uint8_t len = (uint8_t)strlen(gps.nmea_line);
        /* Add \r\n for serial monitor display */
        if (len < sizeof(gps.nmea_line) - 2) {
          gps.nmea_line[len]   = '\r';
          gps.nmea_line[len+1] = '\n';
          CDC_Transmit_FS((uint8_t *)gps.nmea_line, len + 2);
          HAL_Delay(5);
        }
      }

      /* Status line every 5s with RF diagnostics */
      if (now - last_status >= 5000) {
        last_status = now;
        char sbuf[180];
        int slen;

        static const char *ant_str[] = {"INIT","DONTKNOW","OK","SHORT","OPEN"};
        static const char *pwr_str[] = {"OFF","ON","DONTKNOW"};

        if (gps.mon_rf_valid) {
          slen = snprintf(sbuf, sizeof(sbuf),
            ">-- ant=%s pwr=%s agc=%u noise=%u jam=%u | polls=%lu avZ=%lu i2cE=%lu bytes=%lu --\r\n",
            gps.ant_status <= 4 ? ant_str[gps.ant_status] : "?",
            gps.ant_power <= 2 ? pwr_str[gps.ant_power] : "?",
            gps.rf_agc_cnt, gps.rf_noise_per_ms, gps.rf_jam_ind,
            (unsigned long)gps.dbg_polls,
            (unsigned long)gps.dbg_avail_zero,
            (unsigned long)gps.dbg_i2c_err,
            (unsigned long)gps.dbg_bytes_read);
        } else {
          slen = snprintf(sbuf, sizeof(sbuf),
            ">-- ant=? (no MON-RF) | polls=%lu avZ=%lu i2cE=%lu bytes=%lu --\r\n",
            (unsigned long)gps.dbg_polls,
            (unsigned long)gps.dbg_avail_zero,
            (unsigned long)gps.dbg_i2c_err,
            (unsigned long)gps.dbg_bytes_read);
        }
        CDC_Transmit_FS((uint8_t *)sbuf, (uint16_t)slen);
        HAL_GPIO_TogglePin(CONT_YN_1_GPIO_Port, CONT_YN_1_Pin);
      }

      /* Re-poll MON-RF every 30s for fresh RF diagnostics */
      {
        static uint32_t last_rf_poll = 0;
        if (now - last_rf_poll >= 30000) {
          last_rf_poll = now;
          /* Non-blocking: send poll, response parsed in tick_nmea's UBX parser */
          max_m10m_poll_mon_rf(&gps);
        }
      }
    }
#else
    flight_loop_tick();
#endif
  }
  /* USER CODE END 3 */
}

void SystemClock_Config(void)
{
  RCC_OscInitTypeDef RCC_OscInitStruct = {0};
  RCC_ClkInitTypeDef RCC_ClkInitStruct = {0};

  /** Supply configuration update enable
  */
  HAL_PWREx_ConfigSupply(PWR_LDO_SUPPLY);

  /** Configure the main internal regulator output voltage
  */
  __HAL_PWR_VOLTAGESCALING_CONFIG(PWR_REGULATOR_VOLTAGE_SCALE0);

  while(!__HAL_PWR_GET_FLAG(PWR_FLAG_VOSRDY)) {}

  /** Initializes the RCC Oscillators according to the specified parameters
  * in the RCC_OscInitTypeDef structure.
  */
  // WORKAROUND: HSE crystal dead — use HSI (64MHz) as PLL source
  // HSI/4 = 16MHz input, x54 = 864MHz VCO, /2 = 432MHz SYSCLK, /18 = 48MHz USB
  RCC_OscInitStruct.OscillatorType = RCC_OSCILLATORTYPE_HSI;
  RCC_OscInitStruct.HSIState = RCC_HSI_DIV1;
  RCC_OscInitStruct.HSICalibrationValue = RCC_HSICALIBRATION_DEFAULT;
  RCC_OscInitStruct.PLL.PLLState = RCC_PLL_ON;
  RCC_OscInitStruct.PLL.PLLSource = RCC_PLLSOURCE_HSI;
  RCC_OscInitStruct.PLL.PLLM = 4;
  RCC_OscInitStruct.PLL.PLLN = 54;
  RCC_OscInitStruct.PLL.PLLP = 2;
  RCC_OscInitStruct.PLL.PLLQ = 18;
  RCC_OscInitStruct.PLL.PLLR = 4;
  RCC_OscInitStruct.PLL.PLLRGE = RCC_PLL1VCIRANGE_3;
  RCC_OscInitStruct.PLL.PLLVCOSEL = RCC_PLL1VCOWIDE;
  RCC_OscInitStruct.PLL.PLLFRACN = 0;
  if (HAL_RCC_OscConfig(&RCC_OscInitStruct) != HAL_OK)
  {
    Error_Handler();
  }

  /** Initializes the CPU, AHB and APB buses clocks
  */
  RCC_ClkInitStruct.ClockType = RCC_CLOCKTYPE_HCLK|RCC_CLOCKTYPE_SYSCLK
                              |RCC_CLOCKTYPE_PCLK1|RCC_CLOCKTYPE_PCLK2
                              |RCC_CLOCKTYPE_D3PCLK1|RCC_CLOCKTYPE_D1PCLK1;
  RCC_ClkInitStruct.SYSCLKSource = RCC_SYSCLKSOURCE_PLLCLK;
  RCC_ClkInitStruct.SYSCLKDivider = RCC_SYSCLK_DIV1;
  RCC_ClkInitStruct.AHBCLKDivider = RCC_HCLK_DIV2;
  RCC_ClkInitStruct.APB3CLKDivider = RCC_APB3_DIV2;
  RCC_ClkInitStruct.APB1CLKDivider = RCC_APB1_DIV2;
  RCC_ClkInitStruct.APB2CLKDivider = RCC_APB2_DIV2;
  RCC_ClkInitStruct.APB4CLKDivider = RCC_APB4_DIV2;

  if (HAL_RCC_ClockConfig(&RCC_ClkInitStruct, FLASH_LATENCY_4) != HAL_OK)
  {
    Error_Handler();
  }

  /** Enables the Clock Security System
  */
  HAL_RCC_EnableCSS();
}

void PeriphCommonClock_Config(void)
{
  RCC_PeriphCLKInitTypeDef PeriphClkInitStruct = {0};

  /** Initializes the peripherals clock
  */
  PeriphClkInitStruct.PeriphClockSelection = RCC_PERIPHCLK_ADC|RCC_PERIPHCLK_SPI3
                              |RCC_PERIPHCLK_SPI2|RCC_PERIPHCLK_SPI1
                              |RCC_PERIPHCLK_UART4;
  // WORKAROUND: PLL source is HSI (64MHz) — recalculate PLL2 for same 168MHz VCO
  // HSI/8 = 8MHz input, x21 = 168MHz VCO, /2 = 84MHz output (same as HSE config)
  PeriphClkInitStruct.PLL2.PLL2M = 8;
  PeriphClkInitStruct.PLL2.PLL2N = 21;
  PeriphClkInitStruct.PLL2.PLL2P = 2;
  PeriphClkInitStruct.PLL2.PLL2Q = 2;
  PeriphClkInitStruct.PLL2.PLL2R = 2;
  PeriphClkInitStruct.PLL2.PLL2RGE = RCC_PLL2VCIRANGE_3;
  PeriphClkInitStruct.PLL2.PLL2VCOSEL = RCC_PLL2VCOMEDIUM;
  PeriphClkInitStruct.PLL2.PLL2FRACN = 0;
  PeriphClkInitStruct.Spi123ClockSelection = RCC_SPI123CLKSOURCE_PLL2;
  PeriphClkInitStruct.Usart234578ClockSelection = RCC_USART234578CLKSOURCE_PLL2;
  PeriphClkInitStruct.AdcClockSelection = RCC_ADCCLKSOURCE_PLL2;
  if (HAL_RCCEx_PeriphCLKConfig(&PeriphClkInitStruct) != HAL_OK)
  {
    Error_Handler();
  }
}

static void MX_ADC1_Init(void)
{

  ADC_MultiModeTypeDef multimode = {0};
  ADC_ChannelConfTypeDef sConfig = {0};

  /** Common config
  */
  hadc1.Instance = ADC1;
  hadc1.Init.ClockPrescaler = ADC_CLOCK_ASYNC_DIV2;
  hadc1.Init.Resolution = ADC_RESOLUTION_16B;
  hadc1.Init.ScanConvMode = ADC_SCAN_DISABLE;
  hadc1.Init.EOCSelection = ADC_EOC_SINGLE_CONV;
  hadc1.Init.LowPowerAutoWait = DISABLE;
  hadc1.Init.ContinuousConvMode = DISABLE;
  hadc1.Init.NbrOfConversion = 1;
  hadc1.Init.DiscontinuousConvMode = DISABLE;
  hadc1.Init.ExternalTrigConv = ADC_SOFTWARE_START;
  hadc1.Init.ExternalTrigConvEdge = ADC_EXTERNALTRIGCONVEDGE_NONE;
  hadc1.Init.ConversionDataManagement = ADC_CONVERSIONDATA_DR;
  hadc1.Init.Overrun = ADC_OVR_DATA_PRESERVED;
  hadc1.Init.LeftBitShift = ADC_LEFTBITSHIFT_NONE;
  hadc1.Init.OversamplingMode = DISABLE;
  hadc1.Init.Oversampling.Ratio = 1;
  if (HAL_ADC_Init(&hadc1) != HAL_OK)
  {
    Error_Handler();
  }

  /** Configure the ADC multi-mode
  */
  multimode.Mode = ADC_MODE_INDEPENDENT;
  if (HAL_ADCEx_MultiModeConfigChannel(&hadc1, &multimode) != HAL_OK)
  {
    Error_Handler();
  }

  /** Configure Regular Channel
  */
  sConfig.Channel = ADC_CHANNEL_3;
  sConfig.Rank = ADC_REGULAR_RANK_1;
  sConfig.SamplingTime = ADC_SAMPLETIME_1CYCLE_5;
  sConfig.SingleDiff = ADC_SINGLE_ENDED;
  sConfig.OffsetNumber = ADC_OFFSET_NONE;
  sConfig.Offset = 0;
  sConfig.OffsetSignedSaturation = DISABLE;
  if (HAL_ADC_ConfigChannel(&hadc1, &sConfig) != HAL_OK)
  {
    Error_Handler();
  }

}

static void MX_ADC2_Init(void)
{

  ADC_ChannelConfTypeDef sConfig = {0};

  /** Common config
  */
  hadc2.Instance = ADC2;
  hadc2.Init.ClockPrescaler = ADC_CLOCK_ASYNC_DIV2;
  hadc2.Init.Resolution = ADC_RESOLUTION_16B;
  hadc2.Init.ScanConvMode = ADC_SCAN_DISABLE;
  hadc2.Init.EOCSelection = ADC_EOC_SINGLE_CONV;
  hadc2.Init.LowPowerAutoWait = DISABLE;
  hadc2.Init.ContinuousConvMode = DISABLE;
  hadc2.Init.NbrOfConversion = 1;
  hadc2.Init.DiscontinuousConvMode = DISABLE;
  hadc2.Init.ExternalTrigConv = ADC_SOFTWARE_START;
  hadc2.Init.ExternalTrigConvEdge = ADC_EXTERNALTRIGCONVEDGE_NONE;
  hadc2.Init.ConversionDataManagement = ADC_CONVERSIONDATA_DR;
  hadc2.Init.Overrun = ADC_OVR_DATA_PRESERVED;
  hadc2.Init.LeftBitShift = ADC_LEFTBITSHIFT_NONE;
  hadc2.Init.OversamplingMode = DISABLE;
  hadc2.Init.Oversampling.Ratio = 1;
  if (HAL_ADC_Init(&hadc2) != HAL_OK)
  {
    Error_Handler();
  }

  /** Configure Regular Channel
  */
  sConfig.Channel = ADC_CHANNEL_10;
  sConfig.Rank = ADC_REGULAR_RANK_1;
  sConfig.SamplingTime = ADC_SAMPLETIME_1CYCLE_5;
  sConfig.SingleDiff = ADC_SINGLE_ENDED;
  sConfig.OffsetNumber = ADC_OFFSET_NONE;
  sConfig.Offset = 0;
  sConfig.OffsetSignedSaturation = DISABLE;
  if (HAL_ADC_ConfigChannel(&hadc2, &sConfig) != HAL_OK)
  {
    Error_Handler();
  }

}

static void MX_ADC3_Init(void)
{

  ADC_ChannelConfTypeDef sConfig = {0};

  /** Common config
  */
  hadc3.Instance = ADC3;
  hadc3.Init.ClockPrescaler = ADC_CLOCK_ASYNC_DIV2;
  hadc3.Init.Resolution = ADC_RESOLUTION_16B;
  hadc3.Init.ScanConvMode = ADC_SCAN_DISABLE;
  hadc3.Init.EOCSelection = ADC_EOC_SINGLE_CONV;
  hadc3.Init.LowPowerAutoWait = DISABLE;
  hadc3.Init.ContinuousConvMode = DISABLE;
  hadc3.Init.NbrOfConversion = 1;
  hadc3.Init.DiscontinuousConvMode = DISABLE;
  hadc3.Init.ExternalTrigConv = ADC_SOFTWARE_START;
  hadc3.Init.ExternalTrigConvEdge = ADC_EXTERNALTRIGCONVEDGE_NONE;
  hadc3.Init.ConversionDataManagement = ADC_CONVERSIONDATA_DR;
  hadc3.Init.Overrun = ADC_OVR_DATA_PRESERVED;
  hadc3.Init.LeftBitShift = ADC_LEFTBITSHIFT_NONE;
  hadc3.Init.OversamplingMode = DISABLE;
  hadc3.Init.Oversampling.Ratio = 1;
  if (HAL_ADC_Init(&hadc3) != HAL_OK)
  {
    Error_Handler();
  }

  /** Configure Regular Channel
  */
  sConfig.Channel = ADC_CHANNEL_1;
  sConfig.Rank = ADC_REGULAR_RANK_1;
  sConfig.SamplingTime = ADC_SAMPLETIME_1CYCLE_5;
  sConfig.SingleDiff = ADC_SINGLE_ENDED;
  sConfig.OffsetNumber = ADC_OFFSET_NONE;
  sConfig.Offset = 0;
  sConfig.OffsetSignedSaturation = DISABLE;
  if (HAL_ADC_ConfigChannel(&hadc3, &sConfig) != HAL_OK)
  {
    Error_Handler();
  }

}

static void MX_CRC_Init(void)
{

  hcrc.Instance = CRC;
  hcrc.Init.DefaultPolynomialUse = DEFAULT_POLYNOMIAL_ENABLE;
  hcrc.Init.DefaultInitValueUse = DEFAULT_INIT_VALUE_ENABLE;
  hcrc.Init.InputDataInversionMode = CRC_INPUTDATA_INVERSION_NONE;
  hcrc.Init.OutputDataInversionMode = CRC_OUTPUTDATA_INVERSION_DISABLE;
  hcrc.InputDataFormat = CRC_INPUTDATA_FORMAT_BYTES;
  if (HAL_CRC_Init(&hcrc) != HAL_OK)
  {
    Error_Handler();
  }

}

static void MX_I2C1_Init(void)
{

  hi2c1.Instance = I2C1;
  hi2c1.Init.Timing = 0x10707DBC;
  hi2c1.Init.OwnAddress1 = 0;
  hi2c1.Init.AddressingMode = I2C_ADDRESSINGMODE_7BIT;
  hi2c1.Init.DualAddressMode = I2C_DUALADDRESS_DISABLE;
  hi2c1.Init.OwnAddress2 = 0;
  hi2c1.Init.OwnAddress2Masks = I2C_OA2_NOMASK;
  hi2c1.Init.GeneralCallMode = I2C_GENERALCALL_DISABLE;
  hi2c1.Init.NoStretchMode = I2C_NOSTRETCH_DISABLE;
  if (HAL_I2C_Init(&hi2c1) != HAL_OK)
  {
    Error_Handler();
  }

  /** Configure Analogue filter
  */
  if (HAL_I2CEx_ConfigAnalogFilter(&hi2c1, I2C_ANALOGFILTER_ENABLE) != HAL_OK)
  {
    Error_Handler();
  }

  /** Configure Digital filter
  */
  if (HAL_I2CEx_ConfigDigitalFilter(&hi2c1, 0) != HAL_OK)
  {
    Error_Handler();
  }

}

static void MX_I2C2_Init(void)
{

  hi2c2.Instance = I2C2;
  hi2c2.Init.Timing = 0x10707DBC;
  hi2c2.Init.OwnAddress1 = 0;
  hi2c2.Init.AddressingMode = I2C_ADDRESSINGMODE_7BIT;
  hi2c2.Init.DualAddressMode = I2C_DUALADDRESS_DISABLE;
  hi2c2.Init.OwnAddress2 = 0;
  hi2c2.Init.OwnAddress2Masks = I2C_OA2_NOMASK;
  hi2c2.Init.GeneralCallMode = I2C_GENERALCALL_DISABLE;
  hi2c2.Init.NoStretchMode = I2C_NOSTRETCH_DISABLE;
  if (HAL_I2C_Init(&hi2c2) != HAL_OK)
  {
    Error_Handler();
  }

  /** Configure Analogue filter
  */
  if (HAL_I2CEx_ConfigAnalogFilter(&hi2c2, I2C_ANALOGFILTER_ENABLE) != HAL_OK)
  {
    Error_Handler();
  }

  /** Configure Digital filter
  */
  if (HAL_I2CEx_ConfigDigitalFilter(&hi2c2, 0) != HAL_OK)
  {
    Error_Handler();
  }

}

static void MX_I2C3_Init(void)
{

  hi2c3.Instance = I2C3;
  hi2c3.Init.Timing = 0x10707DBC;
  hi2c3.Init.OwnAddress1 = 0;
  hi2c3.Init.AddressingMode = I2C_ADDRESSINGMODE_7BIT;
  hi2c3.Init.DualAddressMode = I2C_DUALADDRESS_DISABLE;
  hi2c3.Init.OwnAddress2 = 0;
  hi2c3.Init.OwnAddress2Masks = I2C_OA2_NOMASK;
  hi2c3.Init.GeneralCallMode = I2C_GENERALCALL_DISABLE;
  hi2c3.Init.NoStretchMode = I2C_NOSTRETCH_DISABLE;
  if (HAL_I2C_Init(&hi2c3) != HAL_OK)
  {
    Error_Handler();
  }

  /** Configure Analogue filter
  */
  if (HAL_I2CEx_ConfigAnalogFilter(&hi2c3, I2C_ANALOGFILTER_ENABLE) != HAL_OK)
  {
    Error_Handler();
  }

  /** Configure Digital filter
  */
  if (HAL_I2CEx_ConfigDigitalFilter(&hi2c3, 0) != HAL_OK)
  {
    Error_Handler();
  }

}

static void MX_QUADSPI_Init(void)
{

  /* QUADSPI parameter configuration*/
  hqspi.Instance = QUADSPI;
  hqspi.Init.ClockPrescaler = 255;
  hqspi.Init.FifoThreshold = 1;
  hqspi.Init.SampleShifting = QSPI_SAMPLE_SHIFTING_NONE;
  hqspi.Init.FlashSize = 1;
  hqspi.Init.ChipSelectHighTime = QSPI_CS_HIGH_TIME_1_CYCLE;
  hqspi.Init.ClockMode = QSPI_CLOCK_MODE_0;
  hqspi.Init.FlashID = QSPI_FLASH_ID_1;
  hqspi.Init.DualFlash = QSPI_DUALFLASH_DISABLE;
  if (HAL_QSPI_Init(&hqspi) != HAL_OK)
  {
    Error_Handler();
  }
  /* USER CODE BEGIN QUADSPI_Init 2 */
  // CubeMX defaults are wrong for W25Q512JV 64MB flash.
  // ClockPrescaler=255 (0.8MHz) → 7 (27MHz), FlashSize=1 → 25 (64MB),
  // SampleShifting → HALFCYCLE, ChipSelectHighTime → 2 cycles.
  hqspi.Init.ClockPrescaler = 7;
  hqspi.Init.FifoThreshold = 4;
  hqspi.Init.SampleShifting = QSPI_SAMPLE_SHIFTING_HALFCYCLE;
  hqspi.Init.FlashSize = 25;
  hqspi.Init.ChipSelectHighTime = QSPI_CS_HIGH_TIME_2_CYCLE;
  HAL_QSPI_Init(&hqspi);
  /* USER CODE END QUADSPI_Init 2 */

}

static void MX_SPI1_Init(void)
{

  /* SPI1 parameter configuration*/
  hspi1.Instance = SPI1;
  hspi1.Init.Mode = SPI_MODE_MASTER;
  hspi1.Init.Direction = SPI_DIRECTION_2LINES;
  hspi1.Init.DataSize = SPI_DATASIZE_8BIT;           /* CubeMX: 4BIT — WRONG */
  hspi1.Init.CLKPolarity = SPI_POLARITY_LOW;
  hspi1.Init.CLKPhase = SPI_PHASE_1EDGE;
  hspi1.Init.NSS = SPI_NSS_SOFT;
  hspi1.Init.BaudRatePrescaler = SPI_BAUDRATEPRESCALER_16; /* CubeMX: 2 — TOO FAST */
  hspi1.Init.FirstBit = SPI_FIRSTBIT_MSB;
  hspi1.Init.TIMode = SPI_TIMODE_DISABLE;
  hspi1.Init.CRCCalculation = SPI_CRCCALCULATION_DISABLE;
  hspi1.Init.CRCPolynomial = 0x0;
  hspi1.Init.NSSPMode = SPI_NSS_PULSE_DISABLE;       /* CubeMX: ENABLE — WRONG */
  hspi1.Init.NSSPolarity = SPI_NSS_POLARITY_LOW;
  hspi1.Init.FifoThreshold = SPI_FIFO_THRESHOLD_01DATA;
  hspi1.Init.TxCRCInitializationPattern = SPI_CRC_INITIALIZATION_ALL_ZERO_PATTERN;
  hspi1.Init.RxCRCInitializationPattern = SPI_CRC_INITIALIZATION_ALL_ZERO_PATTERN;
  hspi1.Init.MasterSSIdleness = SPI_MASTER_SS_IDLENESS_00CYCLE;
  hspi1.Init.MasterInterDataIdleness = SPI_MASTER_INTERDATA_IDLENESS_00CYCLE;
  hspi1.Init.MasterReceiverAutoSusp = SPI_MASTER_RX_AUTOSUSP_DISABLE;
  hspi1.Init.MasterKeepIOState = SPI_MASTER_KEEP_IO_STATE_DISABLE;
  hspi1.Init.IOSwap = SPI_IO_SWAP_DISABLE;
  if (HAL_SPI_Init(&hspi1) != HAL_OK)
  {
    Error_Handler();
  }
  /* USER CODE BEGIN SPI1_Init 2 */
  /* Correct values patched inline above — see "CubeMX: WRONG" comments.
     After CubeMX regen: fix DataSize→8BIT, Prescaler→16, NSSPMode→DISABLE. */
  /* USER CODE END SPI1_Init 2 */

}

static void MX_SPI2_Init(void)
{

  /* SPI2 parameter configuration*/
  hspi2.Instance = SPI2;
  hspi2.Init.Mode = SPI_MODE_MASTER;
  hspi2.Init.Direction = SPI_DIRECTION_2LINES;
  hspi2.Init.DataSize = SPI_DATASIZE_8BIT;
  hspi2.Init.CLKPolarity = SPI_POLARITY_HIGH;
  hspi2.Init.CLKPhase = SPI_PHASE_1EDGE;
  hspi2.Init.NSS = SPI_NSS_SOFT;
  hspi2.Init.BaudRatePrescaler = SPI_BAUDRATEPRESCALER_2;
  hspi2.Init.FirstBit = SPI_FIRSTBIT_MSB;
  hspi2.Init.TIMode = SPI_TIMODE_DISABLE;
  hspi2.Init.CRCCalculation = SPI_CRCCALCULATION_DISABLE;
  hspi2.Init.CRCPolynomial = 0x0;
  hspi2.Init.NSSPMode = SPI_NSS_PULSE_ENABLE;
  hspi2.Init.NSSPolarity = SPI_NSS_POLARITY_LOW;
  hspi2.Init.FifoThreshold = SPI_FIFO_THRESHOLD_01DATA;
  hspi2.Init.TxCRCInitializationPattern = SPI_CRC_INITIALIZATION_ALL_ZERO_PATTERN;
  hspi2.Init.RxCRCInitializationPattern = SPI_CRC_INITIALIZATION_ALL_ZERO_PATTERN;
  hspi2.Init.MasterSSIdleness = SPI_MASTER_SS_IDLENESS_00CYCLE;
  hspi2.Init.MasterInterDataIdleness = SPI_MASTER_INTERDATA_IDLENESS_00CYCLE;
  hspi2.Init.MasterReceiverAutoSusp = SPI_MASTER_RX_AUTOSUSP_DISABLE;
  hspi2.Init.MasterKeepIOState = SPI_MASTER_KEEP_IO_STATE_DISABLE;
  hspi2.Init.IOSwap = SPI_IO_SWAP_DISABLE;
  if (HAL_SPI_Init(&hspi2) != HAL_OK)
  {
    Error_Handler();
  }
  /* USER CODE BEGIN SPI2_Init 2 */
  // LSM6DSO32 requires SPI Mode 3 (CPOL=1, CPHA=1).
  // MasterKeepIOState=ENABLE keeps SCK HIGH (CPOL=1 idle) between transactions,
  // preventing a spurious rising edge when HAL_SPI_TransmitReceive enables the peripheral.
  // CubeMX also reverts BaudRatePrescaler to 2 (42MHz) — LSM6DSO32 max is 10MHz.
  hspi2.Init.CLKPolarity = SPI_POLARITY_HIGH;   // CPOL=1
  hspi2.Init.CLKPhase = SPI_PHASE_2EDGE;        // CPHA=1
  hspi2.Init.BaudRatePrescaler = SPI_BAUDRATEPRESCALER_16;  // PLL2P=84MHz /16 = 5.25MHz
  hspi2.Init.MasterKeepIOState = SPI_MASTER_KEEP_IO_STATE_ENABLE;
  hspi2.Init.NSSPMode = SPI_NSS_PULSE_DISABLE;
  HAL_SPI_Init(&hspi2);
  /* USER CODE END SPI2_Init 2 */

}

static void MX_SPI3_Init(void)
{

  /* SPI3 parameter configuration*/
  hspi3.Instance = SPI3;
  hspi3.Init.Mode = SPI_MODE_MASTER;
  hspi3.Init.Direction = SPI_DIRECTION_2LINES;
  hspi3.Init.DataSize = SPI_DATASIZE_4BIT;
  hspi3.Init.CLKPolarity = SPI_POLARITY_LOW;
  hspi3.Init.CLKPhase = SPI_PHASE_1EDGE;
  hspi3.Init.NSS = SPI_NSS_SOFT;
  hspi3.Init.BaudRatePrescaler = SPI_BAUDRATEPRESCALER_2;
  hspi3.Init.FirstBit = SPI_FIRSTBIT_MSB;
  hspi3.Init.TIMode = SPI_TIMODE_DISABLE;
  hspi3.Init.CRCCalculation = SPI_CRCCALCULATION_DISABLE;
  hspi3.Init.CRCPolynomial = 0x0;
  hspi3.Init.NSSPMode = SPI_NSS_PULSE_ENABLE;
  hspi3.Init.NSSPolarity = SPI_NSS_POLARITY_LOW;
  hspi3.Init.FifoThreshold = SPI_FIFO_THRESHOLD_01DATA;
  hspi3.Init.TxCRCInitializationPattern = SPI_CRC_INITIALIZATION_ALL_ZERO_PATTERN;
  hspi3.Init.RxCRCInitializationPattern = SPI_CRC_INITIALIZATION_ALL_ZERO_PATTERN;
  hspi3.Init.MasterSSIdleness = SPI_MASTER_SS_IDLENESS_00CYCLE;
  hspi3.Init.MasterInterDataIdleness = SPI_MASTER_INTERDATA_IDLENESS_00CYCLE;
  hspi3.Init.MasterReceiverAutoSusp = SPI_MASTER_RX_AUTOSUSP_DISABLE;
  hspi3.Init.MasterKeepIOState = SPI_MASTER_KEEP_IO_STATE_DISABLE;
  hspi3.Init.IOSwap = SPI_IO_SWAP_DISABLE;
  if (HAL_SPI_Init(&hspi3) != HAL_OK)
  {
    Error_Handler();
  }
  /* USER CODE BEGIN SPI3_Init 2 */
  // CubeMX defaults DataSize to 4-bit and BaudRatePrescaler to 2 (42MHz).
  // ADXL372 needs 8-bit data, max 10MHz SPI clock.
  // PLL2P=84MHz / 16 = 5.25MHz — safe for ADXL372.
  hspi3.Init.DataSize = SPI_DATASIZE_8BIT;
  hspi3.Init.BaudRatePrescaler = SPI_BAUDRATEPRESCALER_16;
  HAL_SPI_Init(&hspi3);
  /* USER CODE END SPI3_Init 2 */

}

static void MX_SPI4_Init(void)
{

  /* SPI4 parameter configuration*/
  hspi4.Instance = SPI4;
  hspi4.Init.Mode = SPI_MODE_MASTER;
  hspi4.Init.Direction = SPI_DIRECTION_2LINES;
  hspi4.Init.DataSize = SPI_DATASIZE_4BIT;
  hspi4.Init.CLKPolarity = SPI_POLARITY_LOW;
  hspi4.Init.CLKPhase = SPI_PHASE_1EDGE;
  hspi4.Init.NSS = SPI_NSS_SOFT;
  hspi4.Init.BaudRatePrescaler = SPI_BAUDRATEPRESCALER_2;
  hspi4.Init.FirstBit = SPI_FIRSTBIT_MSB;
  hspi4.Init.TIMode = SPI_TIMODE_DISABLE;
  hspi4.Init.CRCCalculation = SPI_CRCCALCULATION_DISABLE;
  hspi4.Init.CRCPolynomial = 0x0;
  hspi4.Init.NSSPMode = SPI_NSS_PULSE_ENABLE;
  hspi4.Init.NSSPolarity = SPI_NSS_POLARITY_LOW;
  hspi4.Init.FifoThreshold = SPI_FIFO_THRESHOLD_01DATA;
  hspi4.Init.TxCRCInitializationPattern = SPI_CRC_INITIALIZATION_ALL_ZERO_PATTERN;
  hspi4.Init.RxCRCInitializationPattern = SPI_CRC_INITIALIZATION_ALL_ZERO_PATTERN;
  hspi4.Init.MasterSSIdleness = SPI_MASTER_SS_IDLENESS_00CYCLE;
  hspi4.Init.MasterInterDataIdleness = SPI_MASTER_INTERDATA_IDLENESS_00CYCLE;
  hspi4.Init.MasterReceiverAutoSusp = SPI_MASTER_RX_AUTOSUSP_DISABLE;
  hspi4.Init.MasterKeepIOState = SPI_MASTER_KEEP_IO_STATE_DISABLE;
  hspi4.Init.IOSwap = SPI_IO_SWAP_DISABLE;
  if (HAL_SPI_Init(&hspi4) != HAL_OK)
  {
    Error_Handler();
  }
  /* USER CODE BEGIN SPI4_Init 2 */
  // CubeMX reverts DataSize to 4-bit and BaudRatePrescaler to 2 (42MHz).
  // MS5611 needs 8-bit data, max 20MHz SPI clock.
  hspi4.Init.DataSize = SPI_DATASIZE_8BIT;
  hspi4.Init.BaudRatePrescaler = SPI_BAUDRATEPRESCALER_8;  // PLL2P=84MHz /8 = 10.5MHz
  HAL_SPI_Init(&hspi4);
  /* USER CODE END SPI4_Init 2 */

}

static void MX_TIM2_Init(void)
{

  TIM_MasterConfigTypeDef sMasterConfig = {0};
  TIM_OC_InitTypeDef sConfigOC = {0};

  htim2.Instance = TIM2;
  htim2.Init.Prescaler = 0;
  htim2.Init.CounterMode = TIM_COUNTERMODE_UP;
  htim2.Init.Period = 4294967295;
  htim2.Init.ClockDivision = TIM_CLOCKDIVISION_DIV1;
  htim2.Init.AutoReloadPreload = TIM_AUTORELOAD_PRELOAD_DISABLE;
  if (HAL_TIM_PWM_Init(&htim2) != HAL_OK)
  {
    Error_Handler();
  }
  sMasterConfig.MasterOutputTrigger = TIM_TRGO_RESET;
  sMasterConfig.MasterSlaveMode = TIM_MASTERSLAVEMODE_DISABLE;
  if (HAL_TIMEx_MasterConfigSynchronization(&htim2, &sMasterConfig) != HAL_OK)
  {
    Error_Handler();
  }
  sConfigOC.OCMode = TIM_OCMODE_PWM1;
  sConfigOC.Pulse = 0;
  sConfigOC.OCPolarity = TIM_OCPOLARITY_HIGH;
  sConfigOC.OCFastMode = TIM_OCFAST_DISABLE;
  if (HAL_TIM_PWM_ConfigChannel(&htim2, &sConfigOC, TIM_CHANNEL_1) != HAL_OK)
  {
    Error_Handler();
  }
  if (HAL_TIM_PWM_ConfigChannel(&htim2, &sConfigOC, TIM_CHANNEL_2) != HAL_OK)
  {
    Error_Handler();
  }
  if (HAL_TIM_PWM_ConfigChannel(&htim2, &sConfigOC, TIM_CHANNEL_3) != HAL_OK)
  {
    Error_Handler();
  }
  if (HAL_TIM_PWM_ConfigChannel(&htim2, &sConfigOC, TIM_CHANNEL_4) != HAL_OK)
  {
    Error_Handler();
  }
  HAL_TIM_MspPostInit(&htim2);

}

static void MX_TIM4_Init(void)
{

  TIM_MasterConfigTypeDef sMasterConfig = {0};
  TIM_OC_InitTypeDef sConfigOC = {0};

  htim4.Instance = TIM4;
  htim4.Init.Prescaler = 0;
  htim4.Init.CounterMode = TIM_COUNTERMODE_UP;
  htim4.Init.Period = 65535;
  htim4.Init.ClockDivision = TIM_CLOCKDIVISION_DIV1;
  htim4.Init.AutoReloadPreload = TIM_AUTORELOAD_PRELOAD_DISABLE;
  if (HAL_TIM_PWM_Init(&htim4) != HAL_OK)
  {
    Error_Handler();
  }
  sMasterConfig.MasterOutputTrigger = TIM_TRGO_RESET;
  sMasterConfig.MasterSlaveMode = TIM_MASTERSLAVEMODE_DISABLE;
  if (HAL_TIMEx_MasterConfigSynchronization(&htim4, &sMasterConfig) != HAL_OK)
  {
    Error_Handler();
  }
  sConfigOC.OCMode = TIM_OCMODE_PWM1;
  sConfigOC.Pulse = 0;
  sConfigOC.OCPolarity = TIM_OCPOLARITY_HIGH;
  sConfigOC.OCFastMode = TIM_OCFAST_DISABLE;
  if (HAL_TIM_PWM_ConfigChannel(&htim4, &sConfigOC, TIM_CHANNEL_3) != HAL_OK)
  {
    Error_Handler();
  }
  HAL_TIM_MspPostInit(&htim4);

}

static void MX_GPIO_Init(void)
{
  GPIO_InitTypeDef GPIO_InitStruct = {0};

  /* GPIO Ports Clock Enable */
  __HAL_RCC_GPIOE_CLK_ENABLE();
  __HAL_RCC_GPIOC_CLK_ENABLE();
  __HAL_RCC_GPIOH_CLK_ENABLE();
  __HAL_RCC_GPIOA_CLK_ENABLE();
  __HAL_RCC_GPIOB_CLK_ENABLE();
  __HAL_RCC_GPIOD_CLK_ENABLE();

  /*Configure GPIO pin Output Level */
  HAL_GPIO_WritePin(GPIOC, RADIO_NRST_Pin|SPI2_CS_Pin|I2C_3_INT_Pin, GPIO_PIN_RESET);

  /*Configure GPIO pin Output Level */
  HAL_GPIO_WritePin(GPIOB, Radio_CS_Pin|CONT_YN_2_Pin|PY4_Pin, GPIO_PIN_RESET);

  /*Configure GPIO pin Output Level */
  HAL_GPIO_WritePin(GPIOE, CONT_YN_4_Pin|CONT_YN_3_Pin|SPI4_CS_Pin, GPIO_PIN_RESET);

  /*Configure GPIO pin Output Level */
  HAL_GPIO_WritePin(NRST_GPS_GPIO_Port, NRST_GPS_Pin, GPIO_PIN_SET);

  /*Configure GPIO pin Output Level */
  HAL_GPIO_WritePin(GPIOD, PY3_Pin|PY2_Pin|PY1_Pin, GPIO_PIN_RESET);

  /*Configure GPIO pin Output Level */
  HAL_GPIO_WritePin(GPIOA, CONT_YN_1_Pin|SPI3_CS_Pin, GPIO_PIN_RESET);

  /*Configure GPIO pins : RADIO_NRST_Pin SPI2_CS_Pin I2C_3_INT_Pin */
  GPIO_InitStruct.Pin = RADIO_NRST_Pin|SPI2_CS_Pin|I2C_3_INT_Pin;
  GPIO_InitStruct.Mode = GPIO_MODE_OUTPUT_PP;
  GPIO_InitStruct.Pull = GPIO_NOPULL;
  GPIO_InitStruct.Speed = GPIO_SPEED_FREQ_LOW;
  HAL_GPIO_Init(GPIOC, &GPIO_InitStruct);

  /*Configure GPIO pin : SPI2_INT_Pin */
  GPIO_InitStruct.Pin = SPI2_INT_Pin;
  GPIO_InitStruct.Mode = GPIO_MODE_IT_RISING;
  GPIO_InitStruct.Pull = GPIO_NOPULL;
  HAL_GPIO_Init(SPI2_INT_GPIO_Port, &GPIO_InitStruct);

  /*Configure GPIO pin : RADIO_DIO3_Pin */
  GPIO_InitStruct.Pin = RADIO_DIO3_Pin;
  GPIO_InitStruct.Mode = GPIO_MODE_IT_RISING;
  GPIO_InitStruct.Pull = GPIO_NOPULL;
  HAL_GPIO_Init(RADIO_DIO3_GPIO_Port, &GPIO_InitStruct);

  /*Configure GPIO pins : Radio_CS_Pin CONT_YN_2_Pin PY4_Pin */
  GPIO_InitStruct.Pin = Radio_CS_Pin|CONT_YN_2_Pin|PY4_Pin;
  GPIO_InitStruct.Mode = GPIO_MODE_OUTPUT_PP;
  GPIO_InitStruct.Pull = GPIO_NOPULL;
  GPIO_InitStruct.Speed = GPIO_SPEED_FREQ_LOW;
  HAL_GPIO_Init(GPIOB, &GPIO_InitStruct);

  /*Configure GPIO pins : SPI1_INT_Pin RADIO_DIO4_Pin RADIO_DIO5_Pin */
  GPIO_InitStruct.Pin = SPI1_INT_Pin|RADIO_DIO4_Pin|RADIO_DIO5_Pin;
  GPIO_InitStruct.Mode = GPIO_MODE_IT_RISING;
  GPIO_InitStruct.Pull = GPIO_NOPULL;
  HAL_GPIO_Init(GPIOB, &GPIO_InitStruct);

  /*Configure GPIO pins : CONT_YN_4_Pin CONT_YN_3_Pin SPI4_CS_Pin */
  GPIO_InitStruct.Pin = CONT_YN_4_Pin|CONT_YN_3_Pin|SPI4_CS_Pin;
  GPIO_InitStruct.Mode = GPIO_MODE_OUTPUT_PP;
  GPIO_InitStruct.Pull = GPIO_NOPULL;
  GPIO_InitStruct.Speed = GPIO_SPEED_FREQ_LOW;
  HAL_GPIO_Init(GPIOE, &GPIO_InitStruct);

  /*Configure GPIO pin : NRST_GPS_Pin */
  GPIO_InitStruct.Pin = NRST_GPS_Pin;
  GPIO_InitStruct.Mode = GPIO_MODE_OUTPUT_PP;
  GPIO_InitStruct.Pull = GPIO_PULLUP;
  GPIO_InitStruct.Speed = GPIO_SPEED_FREQ_LOW;
  HAL_GPIO_Init(NRST_GPS_GPIO_Port, &GPIO_InitStruct);

  /*Configure GPIO pins : PY3_Pin PY2_Pin PY1_Pin */
  GPIO_InitStruct.Pin = PY3_Pin|PY2_Pin|PY1_Pin;
  GPIO_InitStruct.Mode = GPIO_MODE_OUTPUT_PP;
  GPIO_InitStruct.Pull = GPIO_NOPULL;
  GPIO_InitStruct.Speed = GPIO_SPEED_FREQ_LOW;
  HAL_GPIO_Init(GPIOD, &GPIO_InitStruct);

  /*Configure GPIO pins : CONT_YN_1_Pin SPI3_CS_Pin */
  GPIO_InitStruct.Pin = CONT_YN_1_Pin|SPI3_CS_Pin;
  GPIO_InitStruct.Mode = GPIO_MODE_OUTPUT_PP;
  GPIO_InitStruct.Pull = GPIO_NOPULL;
  GPIO_InitStruct.Speed = GPIO_SPEED_FREQ_LOW;
  HAL_GPIO_Init(GPIOA, &GPIO_InitStruct);

  /*Configure GPIO pins : SPI3_INT_Pin RADIO_DIO2_Pin RADIO_DIO1_Pin */
  GPIO_InitStruct.Pin = SPI3_INT_Pin|RADIO_DIO2_Pin|RADIO_DIO1_Pin;
  GPIO_InitStruct.Mode = GPIO_MODE_IT_RISING;
  GPIO_InitStruct.Pull = GPIO_NOPULL;
  HAL_GPIO_Init(GPIOD, &GPIO_InitStruct);

  /*Configure GPIO pin : GPS_TIMEPULSE_Pin */
  GPIO_InitStruct.Pin = GPS_TIMEPULSE_Pin;
  GPIO_InitStruct.Mode = GPIO_MODE_INPUT;
  GPIO_InitStruct.Pull = GPIO_NOPULL;
  HAL_GPIO_Init(GPS_TIMEPULSE_GPIO_Port, &GPIO_InitStruct);

  /*Configure GPIO pin : I2C1_INT_Pin */
  GPIO_InitStruct.Pin = I2C1_INT_Pin;
  GPIO_InitStruct.Mode = GPIO_MODE_IT_RISING;
  GPIO_InitStruct.Pull = GPIO_NOPULL;
  HAL_GPIO_Init(I2C1_INT_GPIO_Port, &GPIO_InitStruct);

  /* USER CODE BEGIN MX_GPIO_Init_2 */
  // CubeMX groups SPI CS pins with other outputs and sets them LOW.
  // All SPI CS pins must idle HIGH so sensors are deselected.
  HAL_GPIO_WritePin(SPI2_CS_GPIO_Port, SPI2_CS_Pin, GPIO_PIN_SET);
  HAL_GPIO_WritePin(SPI3_CS_GPIO_Port, SPI3_CS_Pin, GPIO_PIN_SET);

  // RADIO_NRST (PC13): CubeMX groups this with SPI2_CS and I2C_3_INT as
  // push-pull output with GPIO_NOPULL and initial state LOW. This holds the
  // SX1276 in reset. PC13 is in the backup domain (3mA max drive) so the
  // rising edge is slow. Fix: reconfigure with GPIO_PULLUP for sharper edges
  // and drive HIGH immediately to release the SX1276 from reset early.
  {
      GPIO_InitTypeDef nrst_fix = {0};
      nrst_fix.Pin   = RADIO_NRST_Pin;
      nrst_fix.Mode  = GPIO_MODE_OUTPUT_PP;
      nrst_fix.Pull  = GPIO_PULLUP;
      nrst_fix.Speed = GPIO_SPEED_FREQ_LOW;
      HAL_GPIO_Init(RADIO_NRST_GPIO_Port, &nrst_fix);
  }
  HAL_GPIO_WritePin(RADIO_NRST_GPIO_Port, RADIO_NRST_Pin, GPIO_PIN_SET);

  // SX1276 DIO4 (PB12) and DIO5 (PB13) were configured as GPIO_MODE_IT_RISING
  // by CubeMX. They share EXTI15_10 with PC15 (LSM6DSO32 INT2), and the radio
  // toggles them constantly during normal operation, causing stale-pending
  // interrupts that previously forced us to disable EXTI15_10 entirely and
  // fall back to a 5 ms STATUS polling watchdog (which capped the IMU service
  // rate at ~166 Hz instead of 833).
  //
  // Note: HAL_GPIO_Init() with GPIO_MODE_INPUT does NOT clear the EXTI line
  // registration in EXTI_IMR / EXTI_RTSR / SYSCFG_EXTICR — those have to be
  // cleared explicitly. Use HAL_GPIO_DeInit() to fully tear down the EXTI
  // configuration, then re-init as plain input. Without the DeInit, the
  // EXTI line keeps firing for radio activity and the main loop is locked
  // up servicing the IRQ.
  HAL_GPIO_DeInit(GPIOB, RADIO_DIO4_Pin | RADIO_DIO5_Pin);
  {
      GPIO_InitTypeDef dio_fix = {0};
      dio_fix.Pin   = RADIO_DIO4_Pin | RADIO_DIO5_Pin;
      dio_fix.Mode  = GPIO_MODE_INPUT;
      dio_fix.Pull  = GPIO_NOPULL;
      dio_fix.Speed = GPIO_SPEED_FREQ_LOW;
      HAL_GPIO_Init(GPIOB, &dio_fix);
  }
  /* Belt-and-braces: clear any EXTI pending bit left over for these pins. */
  __HAL_GPIO_EXTI_CLEAR_IT(RADIO_DIO4_Pin);
  __HAL_GPIO_EXTI_CLEAR_IT(RADIO_DIO5_Pin);
  /* USER CODE END MX_GPIO_Init_2 */
}

/* USER CODE BEGIN 4 */
void HAL_GPIO_EXTI_Callback(uint16_t GPIO_Pin)
{
  /* ---- Radio SX1276 DIO pins ---- */
  if (GPIO_Pin == SPI1_INT_Pin) {   /* PB1  = DIO0 (TxDone/RxDone) */
    g_radio_dio0_flag = 1;
  }
  if (GPIO_Pin == RADIO_DIO1_Pin) { /* PD7  = DIO1 (RxTimeout)     */
    g_radio_dio1_flag = 1;
  }
  if (GPIO_Pin == RADIO_DIO3_Pin) { /* PA4  = DIO3 (ValidHeader)   */
    g_radio_dio3_flag = 1;
  }

  /* ---- GPS data ready (both builds) ---- */
  if (GPIO_Pin == I2C1_INT_Pin) {   /* PE0  = GPS data ready */
    max_m10m_irq_handler(&gps);
  }

#ifndef BUILD_TARGET_GROUND
  /* ---- Flight-only sensor interrupts ---- */
  if (GPIO_Pin == SPI2_INT_Pin) {   /* PC15 = LSM6DSO32 INT2 */
#ifdef LOGGER_SANITY
    extern volatile uint32_t g_imu_exti_fires;
    g_imu_exti_fires++;
#endif
    lsm6dso32_irq_handler(&imu);
  }
  if (GPIO_Pin == I2C_3_INT_Pin) {  /* PC8  = MMC5983MA DRDY */
    mmc5983ma_irq_handler(&mag);
  }
#endif
}
/* USER CODE END 4 */

 /* MPU Configuration */

void MPU_Config(void)
{
  MPU_Region_InitTypeDef MPU_InitStruct = {0};

  /* Disables the MPU */
  HAL_MPU_Disable();

  /** Initializes and configures the Region and the memory to be protected
  */
  MPU_InitStruct.Enable = MPU_REGION_ENABLE;
  MPU_InitStruct.Number = MPU_REGION_NUMBER0;
  MPU_InitStruct.BaseAddress = 0x0;
  MPU_InitStruct.Size = MPU_REGION_SIZE_4GB;
  MPU_InitStruct.SubRegionDisable = 0x87;
  MPU_InitStruct.TypeExtField = MPU_TEX_LEVEL0;
  MPU_InitStruct.AccessPermission = MPU_REGION_NO_ACCESS;
  MPU_InitStruct.DisableExec = MPU_INSTRUCTION_ACCESS_DISABLE;
  MPU_InitStruct.IsShareable = MPU_ACCESS_SHAREABLE;
  MPU_InitStruct.IsCacheable = MPU_ACCESS_NOT_CACHEABLE;
  MPU_InitStruct.IsBufferable = MPU_ACCESS_NOT_BUFFERABLE;

  HAL_MPU_ConfigRegion(&MPU_InitStruct);
  /* Enables the MPU */
  HAL_MPU_Enable(MPU_PRIVILEGED_DEFAULT);

}

void Error_Handler(void)
{
  /* USER CODE BEGIN Error_Handler_Debug */
  /* User can add his own implementation to report the HAL error return state */
  __disable_irq();

  // DIAGNOSTIC: Rapid blink all LEDs to indicate error
  // Enable GPIO clocks (might already be enabled, but safe to call again)
  __HAL_RCC_GPIOE_CLK_ENABLE();
  __HAL_RCC_GPIOB_CLK_ENABLE();
  __HAL_RCC_GPIOA_CLK_ENABLE();

  // Configure all 4 LED pins as GP output (MODER = 01)
  GPIOA->MODER = (GPIOA->MODER & ~(3UL << (10*2))) | (1UL << (10*2)); // PA10
  GPIOB->MODER = (GPIOB->MODER & ~(3UL << (14*2))) | (1UL << (14*2)); // PB14
  GPIOE->MODER = (GPIOE->MODER & ~(3UL << (8*2)))  | (1UL << (8*2));  // PE8
  GPIOE->MODER = (GPIOE->MODER & ~(3UL << (7*2)))  | (1UL << (7*2));  // PE7

  while (1)
  {
      // Very fast blink all LEDs (100ms) = ERROR indication
      HAL_GPIO_WritePin(GPIOE, GPIO_PIN_7, GPIO_PIN_SET);  // YN4
      HAL_GPIO_WritePin(GPIOE, GPIO_PIN_8, GPIO_PIN_SET);  // YN3
      HAL_GPIO_WritePin(GPIOB, GPIO_PIN_14, GPIO_PIN_SET); // YN2
      HAL_GPIO_WritePin(GPIOA, GPIO_PIN_10, GPIO_PIN_SET); // YN1
      for(volatile uint32_t i = 0; i < 500000; i++);  // Software delay

      HAL_GPIO_WritePin(GPIOE, GPIO_PIN_7, GPIO_PIN_RESET);
      HAL_GPIO_WritePin(GPIOE, GPIO_PIN_8, GPIO_PIN_RESET);
      HAL_GPIO_WritePin(GPIOB, GPIO_PIN_14, GPIO_PIN_RESET);
      HAL_GPIO_WritePin(GPIOA, GPIO_PIN_10, GPIO_PIN_RESET);
      for(volatile uint32_t i = 0; i < 500000; i++);
  }
  /* USER CODE END Error_Handler_Debug */
}
